VERSION 5.7 ;
  NOWIREEXTENSIONATPIN ON ;
  DIVIDERCHAR "/" ;
  BUSBITCHARS "[]" ;
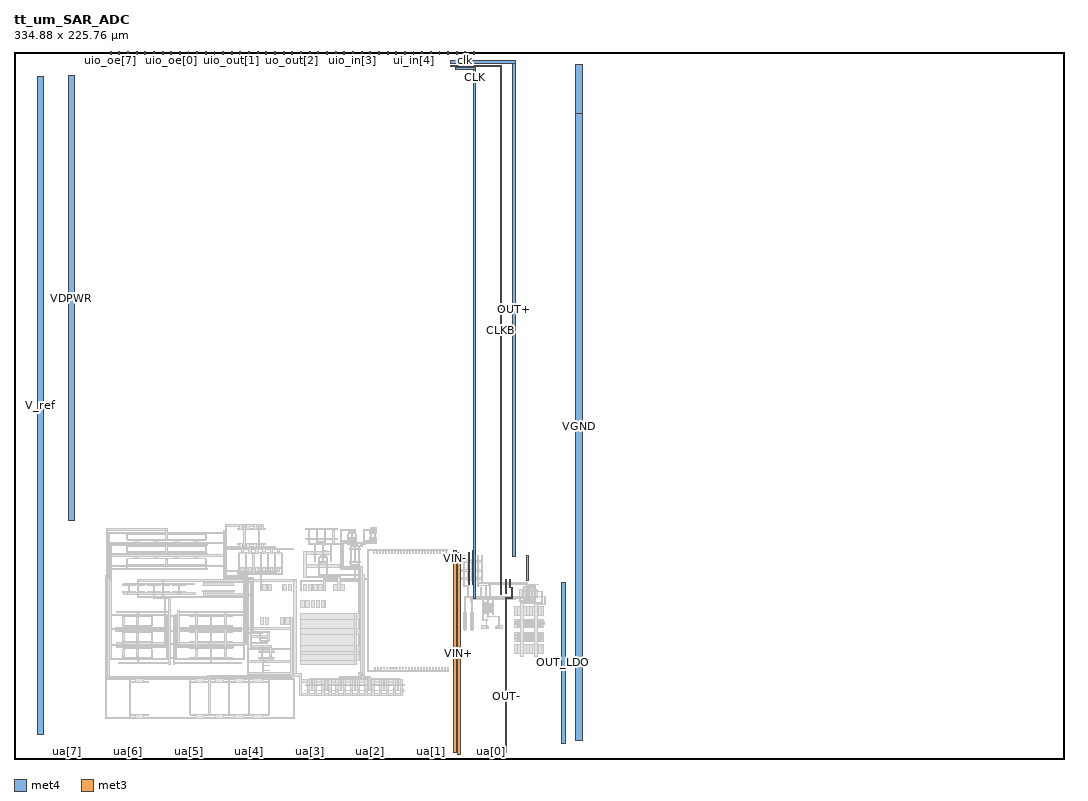
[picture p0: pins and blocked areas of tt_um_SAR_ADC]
MACRO tt_um_SAR_ADC
  CLASS BLOCK ;
  FOREIGN tt_um_SAR_ADC ;
  ORIGIN 0.000 0.000 ;
  SIZE 334.880 BY 225.760 ;
  PIN clk
    DIRECTION INPUT ;
    USE SIGNAL ;
    PORT
      LAYER met4 ;
        RECT 143.830 224.760 144.130 225.760 ;
    END
  END clk
  PIN ena
    DIRECTION INPUT ;
    USE SIGNAL ;
    PORT
      LAYER met4 ;
        RECT 146.590 224.760 146.890 225.760 ;
    END
  END ena
  PIN rst_n
    DIRECTION INPUT ;
    USE SIGNAL ;
    PORT
      LAYER met4 ;
        RECT 141.070 224.760 141.370 225.760 ;
    END
  END rst_n
  PIN ua[0]
    DIRECTION INOUT ;
    USE SIGNAL ;
    PORT
      LAYER met4 ;
        RECT 151.810 0.000 152.710 1.000 ;
    END
  END ua[0]
  PIN ua[1]
    DIRECTION INOUT ;
    USE SIGNAL ;
    PORT
      LAYER met4 ;
        RECT 132.490 0.000 133.390 1.000 ;
    END
  END ua[1]
  PIN ua[2]
    DIRECTION INOUT ;
    USE SIGNAL ;
    PORT
      LAYER met4 ;
        RECT 113.170 0.000 114.070 1.000 ;
    END
  END ua[2]
  PIN ua[3]
    DIRECTION INOUT ;
    USE SIGNAL ;
    PORT
      LAYER met4 ;
        RECT 93.850 0.000 94.750 1.000 ;
    END
  END ua[3]
  PIN ua[4]
    DIRECTION INOUT ;
    USE SIGNAL ;
    PORT
      LAYER met4 ;
        RECT 74.530 0.000 75.430 1.000 ;
    END
  END ua[4]
  PIN ua[5]
    DIRECTION INOUT ;
    USE SIGNAL ;
    PORT
      LAYER met4 ;
        RECT 55.210 0.000 56.110 1.000 ;
    END
  END ua[5]
  PIN ua[6]
    DIRECTION INOUT ;
    USE SIGNAL ;
    PORT
      LAYER met4 ;
        RECT 35.890 0.000 36.790 1.000 ;
    END
  END ua[6]
  PIN ua[7]
    DIRECTION INOUT ;
    USE SIGNAL ;
    PORT
      LAYER met4 ;
        RECT 16.570 0.000 17.470 1.000 ;
    END
  END ua[7]
  PIN ui_in[0]
    DIRECTION INPUT ;
    USE SIGNAL ;
    PORT
      LAYER met4 ;
        RECT 138.310 224.760 138.610 225.760 ;
    END
  END ui_in[0]
  PIN ui_in[1]
    DIRECTION INPUT ;
    USE SIGNAL ;
    PORT
      LAYER met4 ;
        RECT 135.550 224.760 135.850 225.760 ;
    END
  END ui_in[1]
  PIN ui_in[2]
    DIRECTION INPUT ;
    USE SIGNAL ;
    PORT
      LAYER met4 ;
        RECT 132.790 224.760 133.090 225.760 ;
    END
  END ui_in[2]
  PIN ui_in[3]
    DIRECTION INPUT ;
    USE SIGNAL ;
    PORT
      LAYER met4 ;
        RECT 130.030 224.760 130.330 225.760 ;
    END
  END ui_in[3]
  PIN ui_in[4]
    DIRECTION INPUT ;
    USE SIGNAL ;
    PORT
      LAYER met4 ;
        RECT 127.270 224.760 127.570 225.760 ;
    END
  END ui_in[4]
  PIN ui_in[5]
    DIRECTION INPUT ;
    USE SIGNAL ;
    PORT
      LAYER met4 ;
        RECT 124.510 224.760 124.810 225.760 ;
    END
  END ui_in[5]
  PIN ui_in[6]
    DIRECTION INPUT ;
    USE SIGNAL ;
    PORT
      LAYER met4 ;
        RECT 121.750 224.760 122.050 225.760 ;
    END
  END ui_in[6]
  PIN ui_in[7]
    DIRECTION INPUT ;
    USE SIGNAL ;
    PORT
      LAYER met4 ;
        RECT 118.990 224.760 119.290 225.760 ;
    END
  END ui_in[7]
  PIN uio_in[0]
    DIRECTION INPUT ;
    USE SIGNAL ;
    PORT
      LAYER met4 ;
        RECT 116.230 224.760 116.530 225.760 ;
    END
  END uio_in[0]
  PIN uio_in[1]
    DIRECTION INPUT ;
    USE SIGNAL ;
    PORT
      LAYER met4 ;
        RECT 113.470 224.760 113.770 225.760 ;
    END
  END uio_in[1]
  PIN uio_in[2]
    DIRECTION INPUT ;
    USE SIGNAL ;
    PORT
      LAYER met4 ;
        RECT 110.710 224.760 111.010 225.760 ;
    END
  END uio_in[2]
  PIN uio_in[3]
    DIRECTION INPUT ;
    USE SIGNAL ;
    PORT
      LAYER met4 ;
        RECT 107.950 224.760 108.250 225.760 ;
    END
  END uio_in[3]
  PIN uio_in[4]
    DIRECTION INPUT ;
    USE SIGNAL ;
    PORT
      LAYER met4 ;
        RECT 105.190 224.760 105.490 225.760 ;
    END
  END uio_in[4]
  PIN uio_in[5]
    DIRECTION INPUT ;
    USE SIGNAL ;
    PORT
      LAYER met4 ;
        RECT 102.430 224.760 102.730 225.760 ;
    END
  END uio_in[5]
  PIN uio_in[6]
    DIRECTION INPUT ;
    USE SIGNAL ;
    PORT
      LAYER met4 ;
        RECT 99.670 224.760 99.970 225.760 ;
    END
  END uio_in[6]
  PIN uio_in[7]
    DIRECTION INPUT ;
    USE SIGNAL ;
    PORT
      LAYER met4 ;
        RECT 96.910 224.760 97.210 225.760 ;
    END
  END uio_in[7]
  PIN uio_oe[0]
    DIRECTION OUTPUT ;
    USE SIGNAL ;
    PORT
      LAYER met4 ;
        RECT 49.990 224.760 50.290 225.760 ;
    END
  END uio_oe[0]
  PIN uio_oe[1]
    DIRECTION OUTPUT ;
    USE SIGNAL ;
    PORT
      LAYER met4 ;
        RECT 47.230 224.760 47.530 225.760 ;
    END
  END uio_oe[1]
  PIN uio_oe[2]
    DIRECTION OUTPUT ;
    USE SIGNAL ;
    PORT
      LAYER met4 ;
        RECT 44.470 224.760 44.770 225.760 ;
    END
  END uio_oe[2]
  PIN uio_oe[3]
    DIRECTION OUTPUT ;
    USE SIGNAL ;
    PORT
      LAYER met4 ;
        RECT 41.710 224.760 42.010 225.760 ;
    END
  END uio_oe[3]
  PIN uio_oe[4]
    DIRECTION OUTPUT ;
    USE SIGNAL ;
    PORT
      LAYER met4 ;
        RECT 38.950 224.760 39.250 225.760 ;
    END
  END uio_oe[4]
  PIN uio_oe[5]
    DIRECTION OUTPUT ;
    USE SIGNAL ;
    PORT
      LAYER met4 ;
        RECT 36.190 224.760 36.490 225.760 ;
    END
  END uio_oe[5]
  PIN uio_oe[6]
    DIRECTION OUTPUT ;
    USE SIGNAL ;
    PORT
      LAYER met4 ;
        RECT 33.430 224.760 33.730 225.760 ;
    END
  END uio_oe[6]
  PIN uio_oe[7]
    DIRECTION OUTPUT ;
    USE SIGNAL ;
    PORT
      LAYER met4 ;
        RECT 30.670 224.760 30.970 225.760 ;
    END
  END uio_oe[7]
  PIN uio_out[0]
    DIRECTION OUTPUT ;
    USE SIGNAL ;
    PORT
      LAYER met4 ;
        RECT 72.070 224.760 72.370 225.760 ;
    END
  END uio_out[0]
  PIN uio_out[1]
    DIRECTION OUTPUT ;
    USE SIGNAL ;
    PORT
      LAYER met4 ;
        RECT 69.310 224.760 69.610 225.760 ;
    END
  END uio_out[1]
  PIN uio_out[2]
    DIRECTION OUTPUT ;
    USE SIGNAL ;
    PORT
      LAYER met4 ;
        RECT 66.550 224.760 66.850 225.760 ;
    END
  END uio_out[2]
  PIN uio_out[3]
    DIRECTION OUTPUT ;
    USE SIGNAL ;
    PORT
      LAYER met4 ;
        RECT 63.790 224.760 64.090 225.760 ;
    END
  END uio_out[3]
  PIN uio_out[4]
    DIRECTION OUTPUT ;
    USE SIGNAL ;
    PORT
      LAYER met4 ;
        RECT 61.030 224.760 61.330 225.760 ;
    END
  END uio_out[4]
  PIN uio_out[5]
    DIRECTION OUTPUT ;
    USE SIGNAL ;
    PORT
      LAYER met4 ;
        RECT 58.270 224.760 58.570 225.760 ;
    END
  END uio_out[5]
  PIN uio_out[6]
    DIRECTION OUTPUT ;
    USE SIGNAL ;
    PORT
      LAYER met4 ;
        RECT 55.510 224.760 55.810 225.760 ;
    END
  END uio_out[6]
  PIN uio_out[7]
    DIRECTION OUTPUT ;
    USE SIGNAL ;
    PORT
      LAYER met4 ;
        RECT 52.750 224.760 53.050 225.760 ;
    END
  END uio_out[7]
  PIN uo_out[0]
    DIRECTION OUTPUT ;
    USE SIGNAL ;
    PORT
      LAYER met4 ;
        RECT 94.150 224.760 94.450 225.760 ;
    END
  END uo_out[0]
  PIN uo_out[1]
    DIRECTION OUTPUT ;
    USE SIGNAL ;
    PORT
      LAYER met4 ;
        RECT 91.390 224.760 91.690 225.760 ;
    END
  END uo_out[1]
  PIN uo_out[2]
    DIRECTION OUTPUT ;
    USE SIGNAL ;
    PORT
      LAYER met4 ;
        RECT 88.630 224.760 88.930 225.760 ;
    END
  END uo_out[2]
  PIN uo_out[3]
    DIRECTION OUTPUT ;
    USE SIGNAL ;
    PORT
      LAYER met4 ;
        RECT 85.870 224.760 86.170 225.760 ;
    END
  END uo_out[3]
  PIN uo_out[4]
    DIRECTION OUTPUT ;
    USE SIGNAL ;
    PORT
      LAYER met4 ;
        RECT 83.110 224.760 83.410 225.760 ;
    END
  END uo_out[4]
  PIN uo_out[5]
    DIRECTION OUTPUT ;
    USE SIGNAL ;
    PORT
      LAYER met4 ;
        RECT 80.350 224.760 80.650 225.760 ;
    END
  END uo_out[5]
  PIN uo_out[6]
    DIRECTION OUTPUT ;
    USE SIGNAL ;
    PORT
      LAYER met4 ;
        RECT 77.590 224.760 77.890 225.760 ;
    END
  END uo_out[6]
  PIN uo_out[7]
    DIRECTION OUTPUT ;
    USE SIGNAL ;
    PORT
      LAYER met4 ;
        RECT 74.830 224.760 75.130 225.760 ;
    END
  END uo_out[7]
  PIN V_ref
    DIRECTION INPUT ;
    USE POWER ;
    PORT
      LAYER met4 ;
        RECT 7.415 7.755 9.420 217.765 ;
    END
  END V_ref
  PIN VDPWR
    DIRECTION INOUT ;
    USE POWER ;
    PORT
      LAYER met4 ;
        RECT 17.400 75.940 19.400 218.050 ;
    END
  END VDPWR
  PIN VGND
    DIRECTION INOUT ;
    USE GROUND ;
    PORT
      LAYER met4 ;
        RECT 179.160 205.890 181.165 221.595 ;
        RECT 179.160 5.930 181.160 205.890 ;
    END
  END VGND
  PIN CLK
    DIRECTION INOUT ;
    USE CLOCK ;
    ANTENNAGATEAREA 1.497000 ;
    PORT
      LAYER met4 ;
        RECT 140.655 220.015 147.075 220.395 ;
        RECT 146.695 51.275 147.075 220.015 ;
    END
  END CLK
  PIN CLKB
    DIRECTION INOUT ;
    USE CLOCK ;
    ANTENNAGATEAREA 1.260000 ;
    PORT
      LAYER met4 ;
        RECT 139.345 220.950 155.415 221.330 ;
        RECT 155.035 52.380 155.415 220.950 ;
    END
  END CLKB
  PIN OUT_LDO
    DIRECTION OUTPUT ;
    USE SIGNAL ;
    ANTENNAGATEAREA 17.223999 ;
    ANTENNADIFFAREA 346.940796 ;
    PORT
      LAYER met4 ;
        RECT 174.550 5.045 175.860 56.430 ;
    END
  END OUT_LDO
  PIN OUT-
    DIRECTION OUTPUT ;
    USE SIGNAL ;
    ANTENNAGATEAREA 23.000000 ;
    ANTENNADIFFAREA 4.522500 ;
    PORT
      LAYER met3 ;
        RECT 156.620 57.065 156.950 57.395 ;
        RECT 158.115 57.065 158.445 57.395 ;
        RECT 163.325 57.065 164.225 65.055 ;
        RECT 156.635 53.150 156.935 57.065 ;
        RECT 158.130 54.850 158.430 57.065 ;
        RECT 158.130 54.550 158.970 54.850 ;
        RECT 158.670 54.050 158.970 54.550 ;
        RECT 158.655 53.720 158.985 54.050 ;
        RECT 156.620 52.820 156.950 53.150 ;
        RECT 156.690 51.490 157.175 51.540 ;
        RECT 158.670 51.490 158.970 53.720 ;
        RECT 156.690 51.190 158.970 51.490 ;
        RECT 156.690 37.435 157.175 51.190 ;
        RECT 156.690 2.170 157.170 37.435 ;
    END
  END OUT-
  PIN VIN+
    DIRECTION INPUT ;
    USE SIGNAL ;
    ANTENNAGATEAREA 4.620000 ;
    PORT
      LAYER met3 ;
        RECT 141.430 1.525 142.315 65.745 ;
        RECT 144.870 65.400 145.240 65.770 ;
        RECT 144.910 65.055 145.240 65.400 ;
        RECT 144.905 64.915 145.240 65.055 ;
        RECT 144.890 64.665 145.240 64.915 ;
        RECT 144.890 64.585 145.220 64.665 ;
        RECT 144.905 55.975 145.205 64.585 ;
        RECT 144.890 55.645 145.220 55.975 ;
        RECT 144.905 55.590 145.205 55.645 ;
    END
  END VIN+
  PIN VIN-
    DIRECTION OUTPUT ;
    USE SIGNAL ;
    ANTENNAGATEAREA 4.620000 ;
    PORT
      LAYER met3 ;
        RECT 140.155 2.045 141.040 66.515 ;
        RECT 146.305 65.785 146.675 66.555 ;
        RECT 146.340 65.055 146.640 65.785 ;
        RECT 146.320 64.750 146.640 65.055 ;
        RECT 146.320 64.070 146.620 64.750 ;
        RECT 146.305 63.740 146.635 64.070 ;
        RECT 146.320 56.820 146.620 63.740 ;
        RECT 146.305 56.490 146.635 56.820 ;
        RECT 146.320 55.590 146.620 56.490 ;
    END
  END VIN-
  PIN OUT+
    DIRECTION OUTPUT ;
    USE SIGNAL ;
    ANTENNAGATEAREA 23.000000 ;
    ANTENNADIFFAREA 5.772500 ;
    PORT
      LAYER met4 ;
        RECT 139.240 221.805 159.865 222.705 ;
        RECT 158.965 64.660 159.865 221.805 ;
    END
  END OUT+
  OBS
      LAYER pwell ;
        RECT 161.320 51.435 162.260 54.195 ;
        RECT 162.270 51.435 163.210 54.195 ;
        RECT 163.220 51.435 164.160 54.195 ;
        RECT 164.170 51.435 165.110 54.195 ;
        RECT 165.120 51.435 166.060 54.195 ;
        RECT 166.070 51.435 167.010 54.195 ;
        RECT 143.395 41.305 144.335 46.565 ;
        RECT 145.485 41.305 146.425 46.565 ;
        RECT 159.540 45.840 160.480 48.600 ;
        RECT 160.490 45.840 161.430 48.600 ;
        RECT 161.440 45.840 162.380 48.600 ;
        RECT 162.390 45.840 163.330 48.600 ;
        RECT 163.340 45.840 164.280 48.600 ;
        RECT 164.290 45.840 165.230 48.600 ;
        RECT 165.240 45.840 166.180 48.600 ;
        RECT 166.190 45.840 167.130 48.600 ;
        RECT 167.140 45.840 168.080 48.600 ;
        RECT 168.090 45.840 169.030 48.600 ;
        RECT 149.165 41.695 150.955 42.455 ;
        RECT 154.045 41.695 155.835 42.455 ;
        RECT 159.540 41.880 160.480 44.640 ;
        RECT 160.490 41.880 161.430 44.640 ;
        RECT 161.440 41.880 162.380 44.640 ;
        RECT 162.390 41.880 163.330 44.640 ;
        RECT 163.340 41.880 164.280 44.640 ;
        RECT 164.290 41.880 165.230 44.640 ;
        RECT 165.240 41.880 166.180 44.640 ;
        RECT 166.190 41.880 167.130 44.640 ;
        RECT 167.140 41.880 168.080 44.640 ;
        RECT 168.090 41.880 169.030 44.640 ;
        RECT 159.540 37.610 160.480 40.370 ;
        RECT 160.490 37.610 161.430 40.370 ;
        RECT 161.440 37.610 162.380 40.370 ;
        RECT 162.390 37.610 163.330 40.370 ;
        RECT 163.340 37.610 164.280 40.370 ;
        RECT 164.290 37.610 165.230 40.370 ;
        RECT 165.240 37.610 166.180 40.370 ;
        RECT 166.190 37.610 167.130 40.370 ;
        RECT 167.140 37.610 168.080 40.370 ;
        RECT 168.090 37.610 169.030 40.370 ;
        RECT 159.540 33.650 160.480 36.410 ;
        RECT 160.490 33.650 161.430 36.410 ;
        RECT 161.440 33.650 162.380 36.410 ;
        RECT 162.390 33.650 163.330 36.410 ;
        RECT 163.340 33.650 164.280 36.410 ;
        RECT 164.290 33.650 165.230 36.410 ;
        RECT 165.240 33.650 166.180 36.410 ;
        RECT 166.190 33.650 167.130 36.410 ;
        RECT 167.140 33.650 168.080 36.410 ;
        RECT 168.090 33.650 169.030 36.410 ;
      LAYER li1 ;
        RECT 71.380 73.375 73.380 73.545 ;
        RECT 73.670 73.375 75.670 73.545 ;
        RECT 75.960 73.375 77.960 73.545 ;
        RECT 78.250 73.375 80.250 73.545 ;
        RECT 93.010 73.285 94.010 73.455 ;
        RECT 94.300 73.285 95.300 73.455 ;
        RECT 95.590 73.285 96.590 73.455 ;
        RECT 96.880 73.285 97.880 73.455 ;
        RECT 98.170 73.285 99.170 73.455 ;
        RECT 99.460 73.285 100.460 73.455 ;
        RECT 100.750 73.285 101.750 73.455 ;
        RECT 102.040 73.285 103.040 73.455 ;
        RECT 36.205 71.615 42.205 71.785 ;
        RECT 42.495 71.615 48.495 71.785 ;
        RECT 48.785 71.615 54.785 71.785 ;
        RECT 55.075 71.615 61.075 71.785 ;
        RECT 35.975 70.110 36.145 71.400 ;
        RECT 48.555 70.110 48.725 71.400 ;
        RECT 61.135 70.110 61.305 71.400 ;
        RECT 36.205 69.725 42.205 69.895 ;
        RECT 42.495 69.725 48.495 69.895 ;
        RECT 48.785 69.725 54.785 69.895 ;
        RECT 55.075 69.725 61.075 69.895 ;
        RECT 73.440 68.870 73.610 73.160 ;
        RECT 78.020 68.870 78.190 73.160 ;
        RECT 94.070 70.530 94.240 73.070 ;
        RECT 96.650 70.530 96.820 73.070 ;
        RECT 99.230 70.530 99.400 73.070 ;
        RECT 101.810 70.530 101.980 73.070 ;
        RECT 106.750 71.935 107.100 72.105 ;
        RECT 107.390 71.935 107.740 72.105 ;
        RECT 108.030 71.935 108.380 72.105 ;
        RECT 108.670 71.935 109.020 72.105 ;
        RECT 113.470 71.935 113.820 72.105 ;
        RECT 114.110 71.935 114.460 72.105 ;
        RECT 114.750 71.935 115.100 72.105 ;
        RECT 115.390 71.935 115.740 72.105 ;
        RECT 106.520 70.800 106.690 71.720 ;
        RECT 107.800 70.800 107.970 71.720 ;
        RECT 109.080 70.800 109.250 71.720 ;
        RECT 113.880 70.800 114.050 71.720 ;
        RECT 115.160 70.800 115.330 71.720 ;
        RECT 106.750 70.415 107.100 70.585 ;
        RECT 107.390 70.415 107.740 70.585 ;
        RECT 108.030 70.415 108.380 70.585 ;
        RECT 108.670 70.415 109.020 70.585 ;
        RECT 113.470 70.415 113.820 70.585 ;
        RECT 114.110 70.415 114.460 70.585 ;
        RECT 114.750 70.415 115.100 70.585 ;
        RECT 115.390 70.415 115.740 70.585 ;
        RECT 93.010 70.145 94.010 70.315 ;
        RECT 94.300 70.145 95.300 70.315 ;
        RECT 95.590 70.145 96.590 70.315 ;
        RECT 96.880 70.145 97.880 70.315 ;
        RECT 98.170 70.145 99.170 70.315 ;
        RECT 99.460 70.145 100.460 70.315 ;
        RECT 100.750 70.145 101.750 70.315 ;
        RECT 102.040 70.145 103.040 70.315 ;
        RECT 71.380 68.485 73.380 68.655 ;
        RECT 73.670 68.485 75.670 68.655 ;
        RECT 75.960 68.485 77.960 68.655 ;
        RECT 78.250 68.485 80.250 68.655 ;
        RECT 36.205 67.725 42.205 67.895 ;
        RECT 42.495 67.725 48.495 67.895 ;
        RECT 48.785 67.725 54.785 67.895 ;
        RECT 55.075 67.725 61.075 67.895 ;
        RECT 35.975 66.220 36.145 67.510 ;
        RECT 48.555 66.220 48.725 67.510 ;
        RECT 61.135 66.220 61.305 67.510 ;
        RECT 106.870 66.785 107.220 66.955 ;
        RECT 107.510 66.785 107.860 66.955 ;
        RECT 108.150 66.785 108.500 66.955 ;
        RECT 108.790 66.785 109.140 66.955 ;
        RECT 109.430 66.785 109.780 66.955 ;
        RECT 110.070 66.785 110.420 66.955 ;
        RECT 36.205 65.835 42.205 66.005 ;
        RECT 42.495 65.835 48.495 66.005 ;
        RECT 48.785 65.835 54.785 66.005 ;
        RECT 55.075 65.835 61.075 66.005 ;
        RECT 71.935 65.750 73.935 65.920 ;
        RECT 74.225 65.750 76.225 65.920 ;
        RECT 76.515 65.750 78.515 65.920 ;
        RECT 78.805 65.750 80.805 65.920 ;
        RECT 81.095 65.750 83.095 65.920 ;
        RECT 83.385 65.750 85.385 65.920 ;
        RECT 36.205 63.835 42.205 64.005 ;
        RECT 42.495 63.835 48.495 64.005 ;
        RECT 48.785 63.835 54.785 64.005 ;
        RECT 55.075 63.835 61.075 64.005 ;
        RECT 35.975 62.330 36.145 63.620 ;
        RECT 48.555 62.330 48.725 63.620 ;
        RECT 61.135 62.330 61.305 63.620 ;
        RECT 36.205 61.945 42.205 62.115 ;
        RECT 42.495 61.945 48.495 62.115 ;
        RECT 48.785 61.945 54.785 62.115 ;
        RECT 55.075 61.945 61.075 62.115 ;
        RECT 71.705 61.245 71.875 65.535 ;
        RECT 73.995 61.245 74.165 65.535 ;
        RECT 76.285 61.245 76.455 65.535 ;
        RECT 78.575 61.245 78.745 65.535 ;
        RECT 80.865 61.245 81.035 65.535 ;
        RECT 83.155 61.245 83.325 65.535 ;
        RECT 85.445 61.245 85.615 65.535 ;
        RECT 97.480 64.440 98.480 64.610 ;
        RECT 98.770 64.440 99.770 64.610 ;
        RECT 95.960 62.980 96.130 64.270 ;
        RECT 97.250 62.980 97.420 64.270 ;
        RECT 98.540 62.980 98.710 64.270 ;
        RECT 99.830 62.980 100.000 64.270 ;
        RECT 101.120 62.980 101.290 64.270 ;
        RECT 107.280 63.075 107.450 66.615 ;
        RECT 108.560 63.075 108.730 66.615 ;
        RECT 109.840 63.075 110.010 66.615 ;
        RECT 114.630 65.590 114.960 65.760 ;
        RECT 115.590 65.590 115.920 65.760 ;
        RECT 116.550 65.590 116.880 65.760 ;
        RECT 117.510 65.590 117.840 65.760 ;
        RECT 118.470 65.590 118.800 65.760 ;
        RECT 119.430 65.590 119.760 65.760 ;
        RECT 120.390 65.590 120.720 65.760 ;
        RECT 121.350 65.590 121.680 65.760 ;
        RECT 122.310 65.590 122.640 65.760 ;
        RECT 123.270 65.590 123.600 65.760 ;
        RECT 124.230 65.590 124.560 65.760 ;
        RECT 125.190 65.590 125.520 65.760 ;
        RECT 126.150 65.590 126.480 65.760 ;
        RECT 127.110 65.590 127.440 65.760 ;
        RECT 128.070 65.590 128.400 65.760 ;
        RECT 129.030 65.590 129.360 65.760 ;
        RECT 129.990 65.590 130.320 65.760 ;
        RECT 130.950 65.590 131.280 65.760 ;
        RECT 131.910 65.590 132.240 65.760 ;
        RECT 132.870 65.590 133.200 65.760 ;
        RECT 133.830 65.590 134.160 65.760 ;
        RECT 134.790 65.590 135.120 65.760 ;
        RECT 135.750 65.590 136.080 65.760 ;
        RECT 136.710 65.590 137.040 65.760 ;
        RECT 137.670 65.590 138.000 65.760 ;
        RECT 97.480 62.640 98.480 62.810 ;
        RECT 98.770 62.640 99.770 62.810 ;
        RECT 106.870 62.735 107.220 62.905 ;
        RECT 107.510 62.735 107.860 62.905 ;
        RECT 108.150 62.735 108.500 62.905 ;
        RECT 108.790 62.735 109.140 62.905 ;
        RECT 109.430 62.735 109.780 62.905 ;
        RECT 110.070 62.735 110.420 62.905 ;
        RECT 71.935 60.860 73.935 61.030 ;
        RECT 74.225 60.860 76.225 61.030 ;
        RECT 76.515 60.860 78.515 61.030 ;
        RECT 78.805 60.860 80.805 61.030 ;
        RECT 81.095 60.860 83.095 61.030 ;
        RECT 83.385 60.860 85.385 61.030 ;
        RECT 144.550 56.980 144.720 63.580 ;
        RECT 145.180 56.980 145.350 63.580 ;
        RECT 145.810 56.980 145.980 63.580 ;
        RECT 146.440 56.980 146.610 63.580 ;
        RECT 147.070 56.980 147.240 63.580 ;
        RECT 34.495 55.350 36.495 55.520 ;
        RECT 36.785 55.350 38.785 55.520 ;
        RECT 39.635 55.350 41.635 55.520 ;
        RECT 42.485 55.350 44.485 55.520 ;
        RECT 44.775 55.350 46.775 55.520 ;
        RECT 47.625 55.350 49.625 55.520 ;
        RECT 50.475 55.350 52.475 55.520 ;
        RECT 52.765 55.350 54.765 55.520 ;
        RECT 60.215 55.285 61.215 55.455 ;
        RECT 61.505 55.285 62.505 55.455 ;
        RECT 62.795 55.285 63.795 55.455 ;
        RECT 64.085 55.285 65.085 55.455 ;
        RECT 65.375 55.285 66.375 55.455 ;
        RECT 66.665 55.285 67.665 55.455 ;
        RECT 67.955 55.285 68.955 55.455 ;
        RECT 69.245 55.285 70.245 55.455 ;
        RECT 36.555 53.595 36.725 55.135 ;
        RECT 39.405 53.595 39.575 55.135 ;
        RECT 44.545 53.595 44.715 55.135 ;
        RECT 47.395 53.595 47.565 55.135 ;
        RECT 52.535 53.595 52.705 55.135 ;
        RECT 78.485 53.635 78.835 55.795 ;
        RECT 79.315 53.635 79.665 55.795 ;
        RECT 80.145 53.635 80.495 55.795 ;
        RECT 80.975 53.635 81.325 55.795 ;
        RECT 81.805 53.635 82.155 55.795 ;
        RECT 85.775 53.635 86.125 55.795 ;
        RECT 86.605 53.635 86.955 55.795 ;
        RECT 87.435 53.635 87.785 55.795 ;
        RECT 88.265 53.635 88.615 55.795 ;
        RECT 91.405 53.635 91.755 55.795 ;
        RECT 92.235 53.635 92.585 55.795 ;
        RECT 93.065 53.635 93.415 55.795 ;
        RECT 93.895 53.635 94.245 55.795 ;
        RECT 94.725 53.635 95.075 55.795 ;
        RECT 95.555 53.635 95.905 55.795 ;
        RECT 96.385 53.635 96.735 55.795 ;
        RECT 97.215 53.635 97.565 55.795 ;
        RECT 98.045 53.635 98.395 55.795 ;
        RECT 98.875 53.635 99.225 55.795 ;
        RECT 102.015 53.635 102.365 55.795 ;
        RECT 105.155 53.635 105.505 55.795 ;
        RECT 162.575 54.275 162.905 54.505 ;
        RECT 163.525 54.275 163.855 54.505 ;
        RECT 164.475 54.275 164.805 54.505 ;
        RECT 165.425 54.275 165.755 54.505 ;
        RECT 60.215 53.395 61.215 53.565 ;
        RECT 61.505 53.395 62.505 53.565 ;
        RECT 62.795 53.395 63.795 53.565 ;
        RECT 64.085 53.395 65.085 53.565 ;
        RECT 65.375 53.395 66.375 53.565 ;
        RECT 66.665 53.395 67.665 53.565 ;
        RECT 67.955 53.395 68.955 53.565 ;
        RECT 69.245 53.395 70.245 53.565 ;
        RECT 34.495 53.210 36.495 53.380 ;
        RECT 36.785 53.210 38.785 53.380 ;
        RECT 39.635 53.210 41.635 53.380 ;
        RECT 42.485 53.210 44.485 53.380 ;
        RECT 44.775 53.210 46.775 53.380 ;
        RECT 47.625 53.210 49.625 53.380 ;
        RECT 50.475 53.210 52.475 53.380 ;
        RECT 52.765 53.210 54.765 53.380 ;
        RECT 144.645 53.160 144.815 53.660 ;
        RECT 148.770 53.190 148.940 53.610 ;
        RECT 162.440 51.565 162.610 54.065 ;
        RECT 163.390 51.565 163.560 54.065 ;
        RECT 164.340 51.565 164.510 54.065 ;
        RECT 165.290 51.565 165.460 54.065 ;
        RECT 162.575 51.125 162.905 51.355 ;
        RECT 163.525 51.125 163.855 51.355 ;
        RECT 164.475 51.125 164.805 51.355 ;
        RECT 165.425 51.125 165.755 51.355 ;
        RECT 91.405 48.315 91.755 50.475 ;
        RECT 92.235 48.315 92.585 50.475 ;
        RECT 93.065 48.315 93.415 50.475 ;
        RECT 93.895 48.315 94.245 50.475 ;
        RECT 94.725 48.315 95.075 50.475 ;
        RECT 95.555 48.315 95.905 50.475 ;
        RECT 96.385 48.315 96.735 50.475 ;
        RECT 97.215 48.315 97.565 50.475 ;
        RECT 98.045 48.315 98.395 50.475 ;
        RECT 98.875 48.315 99.225 50.475 ;
        RECT 143.625 49.740 143.975 49.970 ;
        RECT 145.935 49.740 146.285 49.970 ;
        RECT 150.110 48.850 150.460 49.080 ;
        RECT 150.740 48.850 151.090 49.080 ;
        RECT 151.370 48.850 151.720 49.080 ;
        RECT 152.000 48.850 152.350 49.080 ;
        RECT 143.625 48.540 143.975 48.770 ;
        RECT 145.935 48.540 146.285 48.770 ;
        RECT 149.885 47.640 150.055 48.640 ;
        RECT 150.515 47.640 150.685 48.640 ;
        RECT 151.145 47.640 151.315 48.640 ;
        RECT 151.775 47.640 151.945 48.640 ;
        RECT 152.405 47.640 152.575 48.640 ;
        RECT 150.110 47.200 150.460 47.430 ;
        RECT 150.740 47.200 151.090 47.430 ;
        RECT 151.370 47.200 151.720 47.430 ;
        RECT 152.000 47.200 152.350 47.430 ;
        RECT 143.700 46.645 144.030 46.875 ;
        RECT 145.790 46.645 146.120 46.875 ;
        RECT 35.025 45.320 37.025 45.490 ;
        RECT 37.315 45.320 39.315 45.490 ;
        RECT 39.605 45.320 41.605 45.490 ;
        RECT 41.895 45.320 43.895 45.490 ;
        RECT 56.115 45.320 58.115 45.490 ;
        RECT 58.405 45.320 60.405 45.490 ;
        RECT 60.695 45.320 62.695 45.490 ;
        RECT 62.985 45.320 64.985 45.490 ;
        RECT 65.275 45.320 67.275 45.490 ;
        RECT 67.565 45.320 69.565 45.490 ;
        RECT 34.795 42.610 34.965 45.150 ;
        RECT 39.375 42.610 39.545 45.150 ;
        RECT 43.955 42.610 44.125 45.150 ;
        RECT 58.175 42.610 58.345 45.150 ;
        RECT 62.755 42.610 62.925 45.150 ;
        RECT 67.335 42.610 67.505 45.150 ;
        RECT 78.485 42.885 78.835 45.045 ;
        RECT 79.315 42.885 79.665 45.045 ;
        RECT 80.145 42.885 80.495 45.045 ;
        RECT 80.975 42.885 81.325 45.045 ;
        RECT 84.945 42.885 85.295 45.045 ;
        RECT 85.775 42.885 86.125 45.045 ;
        RECT 86.605 42.885 86.955 45.045 ;
        RECT 87.435 42.885 87.785 45.045 ;
        RECT 88.265 42.885 88.615 45.045 ;
        RECT 35.025 42.270 37.025 42.440 ;
        RECT 37.315 42.270 39.315 42.440 ;
        RECT 39.605 42.270 41.605 42.440 ;
        RECT 41.895 42.270 43.895 42.440 ;
        RECT 56.115 42.270 58.115 42.440 ;
        RECT 58.405 42.270 60.405 42.440 ;
        RECT 60.695 42.270 62.695 42.440 ;
        RECT 62.985 42.270 64.985 42.440 ;
        RECT 65.275 42.270 67.275 42.440 ;
        RECT 67.565 42.270 69.565 42.440 ;
        RECT 151.135 41.825 151.305 42.325 ;
        RECT 153.695 41.825 153.865 42.325 ;
        RECT 161.090 42.010 161.260 44.510 ;
        RECT 162.040 42.010 162.210 44.510 ;
        RECT 162.990 42.010 163.160 44.510 ;
        RECT 163.940 42.010 164.110 44.510 ;
        RECT 164.890 42.010 165.060 44.510 ;
        RECT 165.840 42.010 166.010 44.510 ;
        RECT 166.790 42.010 166.960 44.510 ;
        RECT 167.740 42.010 167.910 44.510 ;
        RECT 143.700 40.995 144.030 41.225 ;
        RECT 145.790 40.995 146.120 41.225 ;
        RECT 35.025 40.270 37.025 40.440 ;
        RECT 37.315 40.270 39.315 40.440 ;
        RECT 39.605 40.270 41.605 40.440 ;
        RECT 41.895 40.270 43.895 40.440 ;
        RECT 56.115 40.270 58.115 40.440 ;
        RECT 58.405 40.270 60.405 40.440 ;
        RECT 60.695 40.270 62.695 40.440 ;
        RECT 62.985 40.270 64.985 40.440 ;
        RECT 65.275 40.270 67.275 40.440 ;
        RECT 67.565 40.270 69.565 40.440 ;
        RECT 34.795 37.560 34.965 40.100 ;
        RECT 39.375 37.560 39.545 40.100 ;
        RECT 43.955 37.560 44.125 40.100 ;
        RECT 58.175 37.560 58.345 40.100 ;
        RECT 62.755 37.560 62.925 40.100 ;
        RECT 67.335 37.560 67.505 40.100 ;
        RECT 78.725 38.500 79.725 38.670 ;
        RECT 80.015 38.500 81.015 38.670 ;
        RECT 78.495 37.790 78.665 38.330 ;
        RECT 81.075 37.790 81.245 38.330 ;
        RECT 161.090 37.740 161.260 40.240 ;
        RECT 162.040 37.740 162.210 40.240 ;
        RECT 162.990 37.740 163.160 40.240 ;
        RECT 163.940 37.740 164.110 40.240 ;
        RECT 164.890 37.740 165.060 40.240 ;
        RECT 165.840 37.740 166.010 40.240 ;
        RECT 166.790 37.740 166.960 40.240 ;
        RECT 167.740 37.740 167.910 40.240 ;
        RECT 78.725 37.450 79.725 37.620 ;
        RECT 80.015 37.450 81.015 37.620 ;
        RECT 35.025 37.220 37.025 37.390 ;
        RECT 37.315 37.220 39.315 37.390 ;
        RECT 39.605 37.220 41.605 37.390 ;
        RECT 41.895 37.220 43.895 37.390 ;
        RECT 56.115 37.220 58.115 37.390 ;
        RECT 58.405 37.220 60.405 37.390 ;
        RECT 60.695 37.220 62.695 37.390 ;
        RECT 62.985 37.220 64.985 37.390 ;
        RECT 65.275 37.220 67.275 37.390 ;
        RECT 67.565 37.220 69.565 37.390 ;
        RECT 35.025 35.220 37.025 35.390 ;
        RECT 37.315 35.220 39.315 35.390 ;
        RECT 39.605 35.220 41.605 35.390 ;
        RECT 41.895 35.220 43.895 35.390 ;
        RECT 56.115 35.220 58.115 35.390 ;
        RECT 58.405 35.220 60.405 35.390 ;
        RECT 60.695 35.220 62.695 35.390 ;
        RECT 62.985 35.220 64.985 35.390 ;
        RECT 65.275 35.220 67.275 35.390 ;
        RECT 67.565 35.220 69.565 35.390 ;
        RECT 34.795 32.510 34.965 35.050 ;
        RECT 39.375 32.510 39.545 35.050 ;
        RECT 43.955 32.510 44.125 35.050 ;
        RECT 58.175 32.510 58.345 35.050 ;
        RECT 62.755 32.510 62.925 35.050 ;
        RECT 67.335 32.510 67.505 35.050 ;
        RECT 78.070 34.040 79.070 34.210 ;
        RECT 79.360 34.040 80.360 34.210 ;
        RECT 80.650 34.040 81.650 34.210 ;
        RECT 81.940 34.040 82.940 34.210 ;
        RECT 79.130 32.580 79.300 33.870 ;
        RECT 81.710 32.580 81.880 33.870 ;
        RECT 35.025 32.170 37.025 32.340 ;
        RECT 37.315 32.170 39.315 32.340 ;
        RECT 39.605 32.170 41.605 32.340 ;
        RECT 41.895 32.170 43.895 32.340 ;
        RECT 56.115 32.170 58.115 32.340 ;
        RECT 58.405 32.170 60.405 32.340 ;
        RECT 60.695 32.170 62.695 32.340 ;
        RECT 62.985 32.170 64.985 32.340 ;
        RECT 65.275 32.170 67.275 32.340 ;
        RECT 67.565 32.170 69.565 32.340 ;
        RECT 78.070 32.240 79.070 32.410 ;
        RECT 79.360 32.240 80.360 32.410 ;
        RECT 80.650 32.240 81.650 32.410 ;
        RECT 81.940 32.240 82.940 32.410 ;
        RECT 79.630 29.730 81.630 29.900 ;
        RECT 79.400 28.520 79.570 29.560 ;
        RECT 115.110 28.950 115.440 29.120 ;
        RECT 116.070 28.950 116.400 29.120 ;
        RECT 117.030 28.950 117.360 29.120 ;
        RECT 117.990 28.950 118.320 29.120 ;
        RECT 118.950 28.950 119.280 29.120 ;
        RECT 119.910 28.950 120.240 29.120 ;
        RECT 120.870 28.950 121.200 29.120 ;
        RECT 121.830 28.950 122.160 29.120 ;
        RECT 122.790 28.950 123.120 29.120 ;
        RECT 123.750 28.950 124.080 29.120 ;
        RECT 124.710 28.950 125.040 29.120 ;
        RECT 125.670 28.950 126.000 29.120 ;
        RECT 126.630 28.950 126.960 29.120 ;
        RECT 127.590 28.950 127.920 29.120 ;
        RECT 128.550 28.950 128.880 29.120 ;
        RECT 129.510 28.950 129.840 29.120 ;
        RECT 130.470 28.950 130.800 29.120 ;
        RECT 131.430 28.950 131.760 29.120 ;
        RECT 132.390 28.950 132.720 29.120 ;
        RECT 133.350 28.950 133.680 29.120 ;
        RECT 134.310 28.950 134.640 29.120 ;
        RECT 135.270 28.950 135.600 29.120 ;
        RECT 136.230 28.950 136.560 29.120 ;
        RECT 137.190 28.950 137.520 29.120 ;
        RECT 138.150 28.950 138.480 29.120 ;
        RECT 79.630 28.180 81.630 28.350 ;
        RECT 37.055 24.490 43.055 24.660 ;
        RECT 56.185 24.490 62.185 24.660 ;
        RECT 62.475 24.490 68.475 24.660 ;
        RECT 68.765 24.490 74.765 24.660 ;
        RECT 75.055 24.490 81.055 24.660 ;
        RECT 36.825 14.280 36.995 24.320 ;
        RECT 55.955 14.280 56.125 24.320 ;
        RECT 62.245 14.280 62.415 24.320 ;
        RECT 68.535 14.280 68.705 24.320 ;
        RECT 74.825 14.280 74.995 24.320 ;
        RECT 81.115 14.280 81.285 24.320 ;
        RECT 92.915 23.540 94.915 23.710 ;
        RECT 95.205 23.540 97.205 23.710 ;
        RECT 97.495 23.540 99.495 23.710 ;
        RECT 99.785 23.540 101.785 23.710 ;
        RECT 102.075 23.540 104.075 23.710 ;
        RECT 104.365 23.540 106.365 23.710 ;
        RECT 106.655 23.540 108.655 23.710 ;
        RECT 108.945 23.540 110.945 23.710 ;
        RECT 111.235 23.540 113.235 23.710 ;
        RECT 113.525 23.540 115.525 23.710 ;
        RECT 115.815 23.540 117.815 23.710 ;
        RECT 118.105 23.540 120.105 23.710 ;
        RECT 120.395 23.540 122.395 23.710 ;
        RECT 122.685 23.540 124.685 23.710 ;
        RECT 94.975 22.080 95.145 23.370 ;
        RECT 99.555 22.080 99.725 23.370 ;
        RECT 104.135 22.080 104.305 23.370 ;
        RECT 108.715 22.080 108.885 23.370 ;
        RECT 113.295 22.080 113.465 23.370 ;
        RECT 117.875 22.080 118.045 23.370 ;
        RECT 122.455 22.080 122.625 23.370 ;
        RECT 92.915 21.740 94.915 21.910 ;
        RECT 95.205 21.740 97.205 21.910 ;
        RECT 97.495 21.740 99.495 21.910 ;
        RECT 99.785 21.740 101.785 21.910 ;
        RECT 102.075 21.740 104.075 21.910 ;
        RECT 104.365 21.740 106.365 21.910 ;
        RECT 106.655 21.740 108.655 21.910 ;
        RECT 108.945 21.740 110.945 21.910 ;
        RECT 111.235 21.740 113.235 21.910 ;
        RECT 113.525 21.740 115.525 21.910 ;
        RECT 115.815 21.740 117.815 21.910 ;
        RECT 118.105 21.740 120.105 21.910 ;
        RECT 120.395 21.740 122.395 21.910 ;
        RECT 122.685 21.740 124.685 21.910 ;
        RECT 37.055 13.940 43.055 14.110 ;
        RECT 56.185 13.940 62.185 14.110 ;
        RECT 62.475 13.940 68.475 14.110 ;
        RECT 68.765 13.940 74.765 14.110 ;
        RECT 75.055 13.940 81.055 14.110 ;
      LAYER met1 ;
        RECT 72.080 73.575 72.720 73.650 ;
        RECT 74.360 73.575 75.000 73.650 ;
        RECT 76.605 73.575 77.245 73.650 ;
        RECT 78.930 73.575 79.570 73.650 ;
        RECT 71.400 73.345 73.360 73.575 ;
        RECT 73.690 73.345 75.650 73.575 ;
        RECT 75.980 73.345 77.940 73.575 ;
        RECT 78.270 73.345 80.230 73.575 ;
        RECT 72.080 73.280 72.720 73.345 ;
        RECT 74.360 73.280 75.000 73.345 ;
        RECT 76.605 73.280 77.245 73.345 ;
        RECT 78.930 73.280 79.570 73.345 ;
        RECT 93.030 73.255 103.020 73.485 ;
        RECT 73.410 73.080 73.640 73.140 ;
        RECT 77.990 73.080 78.220 73.140 ;
        RECT 38.585 71.815 39.865 72.375 ;
        RECT 44.865 71.815 46.145 72.375 ;
        RECT 51.140 71.815 52.420 72.375 ;
        RECT 57.425 71.815 58.705 72.375 ;
        RECT 36.225 71.585 42.185 71.815 ;
        RECT 42.515 71.585 48.475 71.815 ;
        RECT 48.805 71.585 54.765 71.815 ;
        RECT 55.095 71.585 61.055 71.815 ;
        RECT 35.945 71.320 36.175 71.380 ;
        RECT 48.525 71.320 48.755 71.380 ;
        RECT 61.105 71.320 61.335 71.380 ;
        RECT 35.760 70.190 36.330 71.320 ;
        RECT 48.355 70.190 48.925 71.320 ;
        RECT 60.940 70.190 61.510 71.320 ;
        RECT 35.945 70.130 36.175 70.190 ;
        RECT 48.525 70.130 48.755 70.190 ;
        RECT 61.105 70.130 61.335 70.190 ;
        RECT 36.225 69.695 42.185 69.925 ;
        RECT 42.515 69.695 48.475 69.925 ;
        RECT 48.805 69.695 54.765 69.925 ;
        RECT 55.095 69.695 61.055 69.925 ;
        RECT 38.585 67.925 39.865 69.695 ;
        RECT 44.865 67.925 46.145 69.695 ;
        RECT 51.140 67.925 52.420 69.695 ;
        RECT 57.425 67.925 58.705 69.695 ;
        RECT 73.335 68.950 73.715 73.080 ;
        RECT 77.915 68.950 78.295 73.080 ;
        RECT 94.040 72.990 94.270 73.050 ;
        RECT 93.965 70.610 94.345 72.990 ;
        RECT 94.040 70.550 94.270 70.610 ;
        RECT 96.545 70.345 96.925 73.255 ;
        RECT 99.125 70.345 99.505 73.255 ;
        RECT 101.780 72.990 102.010 73.050 ;
        RECT 101.705 70.610 102.085 72.990 ;
        RECT 106.770 71.905 107.080 73.190 ;
        RECT 107.410 71.905 107.720 73.190 ;
        RECT 108.050 71.905 108.360 73.190 ;
        RECT 108.690 71.905 109.000 73.190 ;
        RECT 113.490 71.905 113.800 73.235 ;
        RECT 114.130 71.905 114.440 73.235 ;
        RECT 114.770 71.905 115.080 73.235 ;
        RECT 115.410 71.905 115.720 73.235 ;
        RECT 106.490 71.640 106.720 71.700 ;
        RECT 107.770 71.640 108.000 71.700 ;
        RECT 109.050 71.640 109.280 71.700 ;
        RECT 113.850 71.640 114.080 71.700 ;
        RECT 115.130 71.640 115.360 71.700 ;
        RECT 106.415 70.880 106.795 71.640 ;
        RECT 107.695 70.880 108.075 71.640 ;
        RECT 108.975 70.880 109.355 71.640 ;
        RECT 113.785 70.880 114.145 71.640 ;
        RECT 115.065 70.880 115.425 71.640 ;
        RECT 106.490 70.820 106.720 70.880 ;
        RECT 107.770 70.820 108.000 70.880 ;
        RECT 109.050 70.820 109.280 70.880 ;
        RECT 113.850 70.820 114.080 70.880 ;
        RECT 115.130 70.820 115.360 70.880 ;
        RECT 101.780 70.550 102.010 70.610 ;
        RECT 93.030 70.115 103.020 70.345 ;
        RECT 106.770 69.345 107.080 70.615 ;
        RECT 107.410 69.345 107.720 70.615 ;
        RECT 108.050 69.340 108.360 70.615 ;
        RECT 108.690 69.345 109.000 70.615 ;
        RECT 113.490 69.300 113.800 70.615 ;
        RECT 114.130 69.300 114.440 70.615 ;
        RECT 114.770 69.300 115.080 70.615 ;
        RECT 115.410 69.300 115.720 70.615 ;
        RECT 73.410 68.890 73.640 68.950 ;
        RECT 77.990 68.890 78.220 68.950 ;
        RECT 72.080 68.685 72.720 68.730 ;
        RECT 74.360 68.685 75.000 68.730 ;
        RECT 76.610 68.685 77.250 68.730 ;
        RECT 78.925 68.685 79.565 68.730 ;
        RECT 71.400 68.455 73.360 68.685 ;
        RECT 73.690 68.455 75.650 68.685 ;
        RECT 75.980 68.455 77.940 68.685 ;
        RECT 78.270 68.455 80.230 68.685 ;
        RECT 72.080 68.360 72.720 68.455 ;
        RECT 74.360 68.360 75.000 68.455 ;
        RECT 76.610 68.360 77.250 68.455 ;
        RECT 78.925 68.360 79.565 68.455 ;
        RECT 36.225 67.695 42.185 67.925 ;
        RECT 42.515 67.695 48.475 67.925 ;
        RECT 48.805 67.695 54.765 67.925 ;
        RECT 55.095 67.695 61.055 67.925 ;
        RECT 35.945 67.430 36.175 67.490 ;
        RECT 48.525 67.430 48.755 67.490 ;
        RECT 61.105 67.430 61.335 67.490 ;
        RECT 35.760 66.300 36.330 67.430 ;
        RECT 48.355 66.300 48.925 67.430 ;
        RECT 60.950 66.300 61.520 67.430 ;
        RECT 106.890 66.755 110.400 66.985 ;
        RECT 107.250 66.535 107.480 66.595 ;
        RECT 35.945 66.240 36.175 66.300 ;
        RECT 48.525 66.240 48.755 66.300 ;
        RECT 61.105 66.240 61.335 66.300 ;
        RECT 36.225 65.805 42.185 66.035 ;
        RECT 42.515 65.805 48.475 66.035 ;
        RECT 48.805 65.805 54.765 66.035 ;
        RECT 55.095 65.805 61.055 66.035 ;
        RECT 72.615 65.950 73.255 66.005 ;
        RECT 74.900 65.950 75.540 66.020 ;
        RECT 77.185 65.950 77.825 66.020 ;
        RECT 79.460 65.950 80.100 66.020 ;
        RECT 81.755 65.950 82.395 66.020 ;
        RECT 84.060 65.950 84.700 66.020 ;
        RECT 38.585 64.035 39.865 65.805 ;
        RECT 44.865 64.035 46.145 65.805 ;
        RECT 51.140 64.035 52.420 65.805 ;
        RECT 57.425 64.035 58.705 65.805 ;
        RECT 71.955 65.720 73.915 65.950 ;
        RECT 74.245 65.720 76.205 65.950 ;
        RECT 76.535 65.720 78.495 65.950 ;
        RECT 78.825 65.720 80.785 65.950 ;
        RECT 81.115 65.720 83.075 65.950 ;
        RECT 83.405 65.720 85.365 65.950 ;
        RECT 72.615 65.635 73.255 65.720 ;
        RECT 74.900 65.650 75.540 65.720 ;
        RECT 77.185 65.650 77.825 65.720 ;
        RECT 79.460 65.650 80.100 65.720 ;
        RECT 81.755 65.650 82.395 65.720 ;
        RECT 84.060 65.650 84.700 65.720 ;
        RECT 71.675 65.455 71.905 65.515 ;
        RECT 73.965 65.455 74.195 65.515 ;
        RECT 76.255 65.455 76.485 65.515 ;
        RECT 78.545 65.455 78.775 65.515 ;
        RECT 80.835 65.455 81.065 65.515 ;
        RECT 83.125 65.455 83.355 65.515 ;
        RECT 85.415 65.455 85.645 65.515 ;
        RECT 36.225 63.805 42.185 64.035 ;
        RECT 42.515 63.805 48.475 64.035 ;
        RECT 48.805 63.805 54.765 64.035 ;
        RECT 55.095 63.805 61.055 64.035 ;
        RECT 35.945 63.540 36.175 63.600 ;
        RECT 48.525 63.540 48.755 63.600 ;
        RECT 61.105 63.540 61.335 63.600 ;
        RECT 35.760 62.410 36.330 63.540 ;
        RECT 48.355 62.410 48.925 63.540 ;
        RECT 60.945 62.410 61.515 63.540 ;
        RECT 35.945 62.350 36.175 62.410 ;
        RECT 48.525 62.350 48.755 62.410 ;
        RECT 61.105 62.350 61.335 62.410 ;
        RECT 36.225 61.915 42.185 62.145 ;
        RECT 42.515 61.915 48.475 62.145 ;
        RECT 48.805 61.915 54.765 62.145 ;
        RECT 55.095 61.915 61.055 62.145 ;
        RECT 38.585 61.355 39.865 61.915 ;
        RECT 44.865 61.355 46.145 61.915 ;
        RECT 51.140 61.355 52.420 61.915 ;
        RECT 57.420 61.520 58.705 61.915 ;
        RECT 57.425 61.355 58.705 61.520 ;
        RECT 71.600 61.325 71.980 65.455 ;
        RECT 73.890 61.325 74.270 65.455 ;
        RECT 76.180 61.325 76.560 65.455 ;
        RECT 78.470 61.325 78.850 65.455 ;
        RECT 80.760 61.325 81.140 65.455 ;
        RECT 83.050 61.325 83.430 65.455 ;
        RECT 85.340 61.325 85.720 65.455 ;
        RECT 97.660 64.640 98.300 66.250 ;
        RECT 98.950 64.640 99.590 66.360 ;
        RECT 97.500 64.410 98.460 64.640 ;
        RECT 98.790 64.410 99.750 64.640 ;
        RECT 95.930 64.190 96.160 64.250 ;
        RECT 97.220 64.190 97.450 64.250 ;
        RECT 98.510 64.190 98.740 64.250 ;
        RECT 95.855 63.060 96.235 64.190 ;
        RECT 97.145 63.060 97.525 64.190 ;
        RECT 98.435 63.060 98.815 64.190 ;
        RECT 99.800 64.185 100.030 64.250 ;
        RECT 101.090 64.190 101.320 64.250 ;
        RECT 95.930 63.000 96.160 63.060 ;
        RECT 97.220 63.000 97.450 63.060 ;
        RECT 98.510 63.000 98.740 63.060 ;
        RECT 99.725 63.055 100.105 64.185 ;
        RECT 101.015 63.060 101.395 64.190 ;
        RECT 107.175 63.155 107.555 66.535 ;
        RECT 107.250 63.095 107.480 63.155 ;
        RECT 99.800 63.000 100.030 63.055 ;
        RECT 101.090 63.000 101.320 63.060 ;
        RECT 108.455 62.935 108.835 66.755 ;
        RECT 109.810 66.570 110.040 66.595 ;
        RECT 109.735 63.190 110.115 66.570 ;
        RECT 114.650 65.560 114.940 66.895 ;
        RECT 115.610 65.560 115.900 66.895 ;
        RECT 116.570 65.560 116.860 66.895 ;
        RECT 117.530 65.560 117.820 66.895 ;
        RECT 118.490 65.560 118.780 66.895 ;
        RECT 119.450 65.560 119.740 66.895 ;
        RECT 120.410 65.560 120.700 66.895 ;
        RECT 121.370 65.560 121.660 66.895 ;
        RECT 122.330 65.560 122.620 66.895 ;
        RECT 123.290 65.560 123.580 66.895 ;
        RECT 124.250 65.560 124.540 66.895 ;
        RECT 125.210 65.560 125.500 66.895 ;
        RECT 126.170 65.560 126.460 66.895 ;
        RECT 127.130 65.560 127.420 66.895 ;
        RECT 128.090 65.560 128.380 66.895 ;
        RECT 129.050 65.560 129.340 66.895 ;
        RECT 130.010 65.560 130.300 66.895 ;
        RECT 130.970 65.560 131.260 66.895 ;
        RECT 131.930 65.560 132.220 66.895 ;
        RECT 132.890 65.560 133.180 66.895 ;
        RECT 133.850 65.560 134.140 66.895 ;
        RECT 134.810 65.560 135.100 66.895 ;
        RECT 135.770 65.560 136.060 66.895 ;
        RECT 136.730 65.560 137.020 66.895 ;
        RECT 137.690 65.560 137.980 66.895 ;
        RECT 109.810 63.095 110.040 63.190 ;
        RECT 97.500 62.610 98.460 62.840 ;
        RECT 98.790 62.610 99.750 62.840 ;
        RECT 106.890 62.705 110.400 62.935 ;
        RECT 71.675 61.265 71.905 61.325 ;
        RECT 73.965 61.265 74.195 61.325 ;
        RECT 76.255 61.265 76.485 61.325 ;
        RECT 78.545 61.265 78.775 61.325 ;
        RECT 80.835 61.265 81.065 61.325 ;
        RECT 83.125 61.265 83.355 61.325 ;
        RECT 85.415 61.265 85.645 61.325 ;
        RECT 72.605 61.060 73.245 61.100 ;
        RECT 74.900 61.060 75.540 61.100 ;
        RECT 77.180 61.060 77.820 61.100 ;
        RECT 79.455 61.060 80.095 61.100 ;
        RECT 81.755 61.060 82.395 61.100 ;
        RECT 84.065 61.060 84.705 61.100 ;
        RECT 71.955 60.830 73.915 61.060 ;
        RECT 74.245 60.830 76.205 61.060 ;
        RECT 76.535 60.830 78.495 61.060 ;
        RECT 78.825 60.830 80.785 61.060 ;
        RECT 81.115 60.830 83.075 61.060 ;
        RECT 83.405 60.830 85.365 61.060 ;
        RECT 97.660 60.995 98.300 62.610 ;
        RECT 98.950 60.995 99.590 62.610 ;
        RECT 72.605 60.730 73.245 60.830 ;
        RECT 74.900 60.730 75.540 60.830 ;
        RECT 77.180 60.730 77.820 60.830 ;
        RECT 79.455 60.730 80.095 60.830 ;
        RECT 81.755 60.730 82.395 60.830 ;
        RECT 84.065 60.730 84.705 60.830 ;
        RECT 144.520 60.455 144.750 63.580 ;
        RECT 144.505 59.815 144.765 60.455 ;
        RECT 144.520 56.980 144.750 59.815 ;
        RECT 145.150 57.860 145.380 63.580 ;
        RECT 145.780 63.415 146.010 63.580 ;
        RECT 145.765 62.775 146.025 63.415 ;
        RECT 145.135 57.220 145.395 57.860 ;
        RECT 145.150 56.980 145.380 57.220 ;
        RECT 145.780 56.980 146.010 62.775 ;
        RECT 146.410 57.860 146.640 63.580 ;
        RECT 147.040 60.455 147.270 63.580 ;
        RECT 147.025 59.815 147.285 60.455 ;
        RECT 146.395 57.220 146.655 57.860 ;
        RECT 146.410 56.980 146.640 57.220 ;
        RECT 147.040 56.980 147.270 59.815 ;
        RECT 34.900 55.550 36.180 56.110 ;
        RECT 37.110 55.550 38.390 56.110 ;
        RECT 39.995 55.550 41.275 56.110 ;
        RECT 42.875 55.550 44.155 56.110 ;
        RECT 45.145 55.550 46.425 56.110 ;
        RECT 47.925 55.550 49.205 56.110 ;
        RECT 50.855 55.550 52.135 56.110 ;
        RECT 53.130 55.550 54.410 56.110 ;
        RECT 34.515 55.320 36.475 55.550 ;
        RECT 36.805 55.320 38.765 55.550 ;
        RECT 39.655 55.320 41.615 55.550 ;
        RECT 42.505 55.320 44.465 55.550 ;
        RECT 44.795 55.320 46.755 55.550 ;
        RECT 47.645 55.320 49.605 55.550 ;
        RECT 50.495 55.320 52.455 55.550 ;
        RECT 52.785 55.320 54.745 55.550 ;
        RECT 60.400 55.485 61.040 56.555 ;
        RECT 61.680 55.485 62.320 56.555 ;
        RECT 62.980 55.485 63.620 56.555 ;
        RECT 64.265 55.485 64.905 56.555 ;
        RECT 65.535 55.485 66.175 56.555 ;
        RECT 66.840 55.485 67.480 56.555 ;
        RECT 68.135 56.540 68.775 56.555 ;
        RECT 69.425 56.540 70.065 56.555 ;
        RECT 68.115 56.210 68.775 56.540 ;
        RECT 69.400 56.210 70.065 56.540 ;
        RECT 68.135 55.485 68.775 56.210 ;
        RECT 69.425 55.485 70.065 56.210 ;
        RECT 78.535 55.705 78.785 55.765 ;
        RECT 60.235 55.255 61.195 55.485 ;
        RECT 61.525 55.255 62.485 55.485 ;
        RECT 62.815 55.255 63.775 55.485 ;
        RECT 64.105 55.255 65.065 55.485 ;
        RECT 65.395 55.255 66.355 55.485 ;
        RECT 66.685 55.255 67.645 55.485 ;
        RECT 67.975 55.255 68.935 55.485 ;
        RECT 69.265 55.255 70.225 55.485 ;
        RECT 36.525 55.055 36.755 55.115 ;
        RECT 39.375 55.055 39.605 55.115 ;
        RECT 44.515 55.055 44.745 55.115 ;
        RECT 47.365 55.055 47.595 55.115 ;
        RECT 52.505 55.055 52.735 55.115 ;
        RECT 36.450 53.675 36.830 55.055 ;
        RECT 39.300 53.675 39.680 55.055 ;
        RECT 44.440 53.675 44.820 55.055 ;
        RECT 47.290 53.675 47.670 55.055 ;
        RECT 52.430 53.675 52.810 55.055 ;
        RECT 78.470 53.720 78.850 55.705 ;
        RECT 36.525 53.615 36.755 53.675 ;
        RECT 39.375 53.615 39.605 53.675 ;
        RECT 44.515 53.615 44.745 53.675 ;
        RECT 47.365 53.615 47.595 53.675 ;
        RECT 52.505 53.615 52.735 53.675 ;
        RECT 78.535 53.660 78.785 53.720 ;
        RECT 79.365 53.660 80.445 55.765 ;
        RECT 81.025 53.660 82.105 55.765 ;
        RECT 85.825 53.660 86.905 55.765 ;
        RECT 87.485 53.660 88.565 55.765 ;
        RECT 91.455 55.700 91.705 55.765 ;
        RECT 91.390 53.715 91.770 55.700 ;
        RECT 91.455 53.660 91.705 53.715 ;
        RECT 92.285 53.660 93.365 55.765 ;
        RECT 93.945 53.660 95.025 55.765 ;
        RECT 95.605 53.660 96.685 55.765 ;
        RECT 97.265 53.660 98.345 55.765 ;
        RECT 98.925 55.705 99.175 55.765 ;
        RECT 102.065 55.745 102.315 55.765 ;
        RECT 105.205 55.755 105.455 55.765 ;
        RECT 98.860 53.720 99.240 55.705 ;
        RECT 98.925 53.660 99.175 53.720 ;
        RECT 101.980 53.680 102.400 55.745 ;
        RECT 105.125 53.690 105.545 55.755 ;
        RECT 162.575 54.255 162.905 54.945 ;
        RECT 163.525 54.255 163.855 54.525 ;
        RECT 164.475 54.255 164.805 54.525 ;
        RECT 165.425 54.255 165.755 54.945 ;
        RECT 102.065 53.660 102.315 53.680 ;
        RECT 105.205 53.660 105.455 53.690 ;
        RECT 34.515 53.180 36.475 53.410 ;
        RECT 36.805 53.180 38.765 53.410 ;
        RECT 39.655 53.180 41.615 53.410 ;
        RECT 42.505 53.180 44.465 53.410 ;
        RECT 44.795 53.180 46.755 53.410 ;
        RECT 47.645 53.180 49.605 53.410 ;
        RECT 50.495 53.180 52.455 53.410 ;
        RECT 52.785 53.180 54.745 53.410 ;
        RECT 60.235 53.365 61.195 53.595 ;
        RECT 61.525 53.365 62.485 53.595 ;
        RECT 62.815 53.365 63.775 53.595 ;
        RECT 64.105 53.365 65.065 53.595 ;
        RECT 65.395 53.365 66.355 53.595 ;
        RECT 66.685 53.365 67.645 53.595 ;
        RECT 67.975 53.365 68.935 53.595 ;
        RECT 69.265 53.365 70.225 53.595 ;
        RECT 144.590 53.450 144.910 53.710 ;
        RECT 148.740 53.555 148.970 53.610 ;
        RECT 162.410 53.560 162.640 54.065 ;
        RECT 34.900 52.620 36.180 53.180 ;
        RECT 37.110 52.620 38.390 53.180 ;
        RECT 39.995 52.620 41.275 53.180 ;
        RECT 42.875 52.620 44.155 53.180 ;
        RECT 45.145 52.620 46.425 53.180 ;
        RECT 47.925 52.620 49.205 53.180 ;
        RECT 50.855 52.620 52.135 53.180 ;
        RECT 53.130 52.620 54.410 53.180 ;
        RECT 60.400 52.295 61.040 53.365 ;
        RECT 61.680 52.295 62.320 53.365 ;
        RECT 62.980 52.295 63.620 53.365 ;
        RECT 64.265 52.295 64.905 53.365 ;
        RECT 65.535 52.295 66.175 53.365 ;
        RECT 66.840 52.295 67.480 53.365 ;
        RECT 68.135 52.295 68.775 53.365 ;
        RECT 69.425 52.295 70.065 53.365 ;
        RECT 144.615 53.160 144.845 53.450 ;
        RECT 148.725 53.235 148.985 53.555 ;
        RECT 162.395 53.240 162.655 53.560 ;
        RECT 148.740 53.190 148.970 53.235 ;
        RECT 162.410 51.565 162.640 53.240 ;
        RECT 163.360 51.900 163.590 54.065 ;
        RECT 164.310 51.900 164.540 54.065 ;
        RECT 165.260 53.560 165.490 54.065 ;
        RECT 165.245 53.240 165.505 53.560 ;
        RECT 163.345 51.570 163.605 51.900 ;
        RECT 164.295 51.570 164.555 51.900 ;
        RECT 163.360 51.565 163.590 51.570 ;
        RECT 164.310 51.565 164.540 51.570 ;
        RECT 165.260 51.565 165.490 53.240 ;
        RECT 162.575 50.665 162.905 51.375 ;
        RECT 163.525 51.105 163.855 51.375 ;
        RECT 164.475 51.105 164.805 51.375 ;
        RECT 165.425 50.665 165.755 51.375 ;
        RECT 91.455 48.345 92.535 50.450 ;
        RECT 93.115 48.345 94.195 50.450 ;
        RECT 94.775 48.345 95.855 50.450 ;
        RECT 96.435 48.345 97.515 50.450 ;
        RECT 98.095 48.345 99.175 50.450 ;
        RECT 143.625 49.720 143.975 49.990 ;
        RECT 145.935 49.720 146.285 49.990 ;
        RECT 150.110 48.830 150.460 49.545 ;
        RECT 150.740 48.830 151.090 49.100 ;
        RECT 151.370 48.830 151.720 49.100 ;
        RECT 152.000 48.830 152.350 49.545 ;
        RECT 143.625 48.520 143.975 48.790 ;
        RECT 145.935 48.520 146.285 48.790 ;
        RECT 149.855 47.910 150.085 48.640 ;
        RECT 150.470 48.370 150.730 48.690 ;
        RECT 149.840 47.590 150.100 47.910 ;
        RECT 150.485 47.640 150.715 48.370 ;
        RECT 151.115 48.285 151.345 48.640 ;
        RECT 151.730 48.350 151.990 48.670 ;
        RECT 151.100 47.965 151.360 48.285 ;
        RECT 151.115 47.640 151.345 47.965 ;
        RECT 151.745 47.640 151.975 48.350 ;
        RECT 152.375 47.880 152.605 48.640 ;
        RECT 152.330 47.620 152.650 47.880 ;
        RECT 143.700 46.625 144.030 46.895 ;
        RECT 145.790 46.625 146.120 46.895 ;
        RECT 150.110 46.735 150.460 47.450 ;
        RECT 150.740 47.180 151.090 47.450 ;
        RECT 151.370 47.180 151.720 47.450 ;
        RECT 152.000 46.780 152.350 47.450 ;
        RECT 35.705 45.520 36.345 46.080 ;
        RECT 38.010 45.520 38.650 46.080 ;
        RECT 40.300 45.520 40.940 46.090 ;
        RECT 42.585 45.520 43.225 46.080 ;
        RECT 56.805 45.520 57.445 46.085 ;
        RECT 59.090 45.520 59.730 46.085 ;
        RECT 61.380 45.520 62.020 46.085 ;
        RECT 63.655 45.520 64.295 46.085 ;
        RECT 65.955 45.520 66.595 46.085 ;
        RECT 68.240 45.520 68.880 46.085 ;
        RECT 35.045 45.290 37.005 45.520 ;
        RECT 37.335 45.290 39.295 45.520 ;
        RECT 39.625 45.290 41.585 45.520 ;
        RECT 41.915 45.290 43.875 45.520 ;
        RECT 56.135 45.290 58.095 45.520 ;
        RECT 58.425 45.290 60.385 45.520 ;
        RECT 60.715 45.290 62.675 45.520 ;
        RECT 63.005 45.290 64.965 45.520 ;
        RECT 65.295 45.290 67.255 45.520 ;
        RECT 67.585 45.290 69.545 45.520 ;
        RECT 34.765 45.025 34.995 45.130 ;
        RECT 39.345 45.025 39.575 45.130 ;
        RECT 43.925 45.025 44.155 45.130 ;
        RECT 34.645 42.750 35.115 45.025 ;
        RECT 39.225 42.750 39.695 45.025 ;
        RECT 43.810 42.750 44.280 45.025 ;
        RECT 34.765 42.630 34.995 42.750 ;
        RECT 39.345 42.630 39.575 42.750 ;
        RECT 43.925 42.630 44.155 42.750 ;
        RECT 58.025 42.630 58.495 45.130 ;
        RECT 62.600 42.630 63.070 45.130 ;
        RECT 67.185 42.630 67.655 45.130 ;
        RECT 78.535 42.915 79.615 45.020 ;
        RECT 80.195 42.915 81.275 45.020 ;
        RECT 84.995 42.915 86.075 45.020 ;
        RECT 86.655 42.915 87.735 45.020 ;
        RECT 88.315 44.960 88.565 45.020 ;
        RECT 88.250 42.975 88.630 44.960 ;
        RECT 161.060 43.855 161.290 44.510 ;
        RECT 161.045 43.525 161.305 43.855 ;
        RECT 88.315 42.915 88.565 42.975 ;
        RECT 35.045 42.240 37.005 42.470 ;
        RECT 37.335 42.240 39.295 42.470 ;
        RECT 39.625 42.240 41.585 42.470 ;
        RECT 41.915 42.240 43.875 42.470 ;
        RECT 56.135 42.240 58.095 42.470 ;
        RECT 58.425 42.240 60.385 42.470 ;
        RECT 60.715 42.240 62.675 42.470 ;
        RECT 63.005 42.240 64.965 42.470 ;
        RECT 65.295 42.240 67.255 42.470 ;
        RECT 67.585 42.240 69.545 42.470 ;
        RECT 35.705 40.470 36.345 42.240 ;
        RECT 38.010 40.470 38.650 42.240 ;
        RECT 40.300 40.470 40.940 42.240 ;
        RECT 42.585 40.470 43.225 42.240 ;
        RECT 56.805 40.470 57.445 42.240 ;
        RECT 59.090 40.470 59.730 42.240 ;
        RECT 61.380 40.470 62.020 42.240 ;
        RECT 63.655 40.470 64.295 42.240 ;
        RECT 65.955 40.470 66.595 42.240 ;
        RECT 68.240 40.470 68.880 42.240 ;
        RECT 151.105 42.035 151.335 42.325 ;
        RECT 153.665 42.035 153.895 42.325 ;
        RECT 151.060 41.775 151.380 42.035 ;
        RECT 153.620 41.775 153.940 42.035 ;
        RECT 161.060 42.010 161.290 43.525 ;
        RECT 162.010 43.085 162.240 44.510 ;
        RECT 162.960 43.085 163.190 44.510 ;
        RECT 163.910 43.855 164.140 44.510 ;
        RECT 164.860 43.855 165.090 44.510 ;
        RECT 163.895 43.525 164.155 43.855 ;
        RECT 164.845 43.525 165.105 43.855 ;
        RECT 161.995 42.755 162.255 43.085 ;
        RECT 162.945 42.755 163.205 43.085 ;
        RECT 162.010 42.010 162.240 42.755 ;
        RECT 162.960 42.010 163.190 42.755 ;
        RECT 163.910 42.010 164.140 43.525 ;
        RECT 164.860 42.010 165.090 43.525 ;
        RECT 165.810 43.085 166.040 44.510 ;
        RECT 166.760 43.085 166.990 44.510 ;
        RECT 167.710 43.855 167.940 44.510 ;
        RECT 167.695 43.525 167.955 43.855 ;
        RECT 165.795 42.755 166.055 43.085 ;
        RECT 166.745 42.755 167.005 43.085 ;
        RECT 165.810 42.010 166.040 42.755 ;
        RECT 166.760 42.010 166.990 42.755 ;
        RECT 167.710 42.010 167.940 43.525 ;
        RECT 143.700 40.975 144.030 41.245 ;
        RECT 145.790 41.240 146.120 41.245 ;
        RECT 145.790 40.980 146.135 41.240 ;
        RECT 145.790 40.975 146.120 40.980 ;
        RECT 35.045 40.240 37.005 40.470 ;
        RECT 37.335 40.240 39.295 40.470 ;
        RECT 39.625 40.240 41.585 40.470 ;
        RECT 41.915 40.240 43.875 40.470 ;
        RECT 56.135 40.240 58.095 40.470 ;
        RECT 58.425 40.240 60.385 40.470 ;
        RECT 60.715 40.240 62.675 40.470 ;
        RECT 63.005 40.240 64.965 40.470 ;
        RECT 65.295 40.240 67.255 40.470 ;
        RECT 67.585 40.240 69.545 40.470 ;
        RECT 34.765 39.965 34.995 40.080 ;
        RECT 39.345 39.970 39.575 40.080 ;
        RECT 43.925 39.970 44.155 40.080 ;
        RECT 34.645 37.690 35.115 39.965 ;
        RECT 39.225 37.695 39.695 39.970 ;
        RECT 43.810 37.695 44.280 39.970 ;
        RECT 34.765 37.580 34.995 37.690 ;
        RECT 39.345 37.580 39.575 37.695 ;
        RECT 43.925 37.580 44.155 37.695 ;
        RECT 58.025 37.580 58.495 40.080 ;
        RECT 62.595 37.740 63.080 40.080 ;
        RECT 67.170 37.740 67.655 40.080 ;
        RECT 161.060 39.585 161.290 40.240 ;
        RECT 78.920 38.700 79.560 39.260 ;
        RECT 80.190 38.700 80.830 39.260 ;
        RECT 161.045 39.255 161.305 39.585 ;
        RECT 78.745 38.470 79.705 38.700 ;
        RECT 80.035 38.470 80.995 38.700 ;
        RECT 78.465 38.250 78.695 38.310 ;
        RECT 81.045 38.250 81.275 38.310 ;
        RECT 78.390 37.870 78.770 38.250 ;
        RECT 80.970 37.870 81.350 38.250 ;
        RECT 78.465 37.810 78.695 37.870 ;
        RECT 81.045 37.810 81.275 37.870 ;
        RECT 161.060 37.740 161.290 39.255 ;
        RECT 162.010 38.815 162.240 40.240 ;
        RECT 162.960 38.815 163.190 40.240 ;
        RECT 163.910 39.585 164.140 40.240 ;
        RECT 164.860 39.585 165.090 40.240 ;
        RECT 163.895 39.255 164.155 39.585 ;
        RECT 164.845 39.255 165.105 39.585 ;
        RECT 161.995 38.485 162.255 38.815 ;
        RECT 162.945 38.485 163.205 38.815 ;
        RECT 162.010 37.740 162.240 38.485 ;
        RECT 162.960 37.740 163.190 38.485 ;
        RECT 163.910 37.740 164.140 39.255 ;
        RECT 164.860 37.740 165.090 39.255 ;
        RECT 165.810 38.815 166.040 40.240 ;
        RECT 166.760 38.815 166.990 40.240 ;
        RECT 167.710 39.585 167.940 40.240 ;
        RECT 167.695 39.255 167.955 39.585 ;
        RECT 165.795 38.485 166.055 38.815 ;
        RECT 166.745 38.485 167.005 38.815 ;
        RECT 165.810 37.740 166.040 38.485 ;
        RECT 166.760 37.740 166.990 38.485 ;
        RECT 167.710 37.740 167.940 39.255 ;
        RECT 62.725 37.580 62.955 37.740 ;
        RECT 67.305 37.580 67.535 37.740 ;
        RECT 78.745 37.420 79.705 37.650 ;
        RECT 80.035 37.420 80.995 37.650 ;
        RECT 35.045 37.190 37.005 37.420 ;
        RECT 37.335 37.190 39.295 37.420 ;
        RECT 39.625 37.190 41.585 37.420 ;
        RECT 41.915 37.190 43.875 37.420 ;
        RECT 56.135 37.190 58.095 37.420 ;
        RECT 58.425 37.190 60.385 37.420 ;
        RECT 60.715 37.190 62.675 37.420 ;
        RECT 63.005 37.190 64.965 37.420 ;
        RECT 65.295 37.190 67.255 37.420 ;
        RECT 67.585 37.190 69.545 37.420 ;
        RECT 35.705 35.420 36.345 37.190 ;
        RECT 38.010 35.420 38.650 37.190 ;
        RECT 40.300 35.420 40.940 37.190 ;
        RECT 42.585 35.420 43.225 37.190 ;
        RECT 56.805 35.420 57.445 37.190 ;
        RECT 59.090 35.420 59.730 37.190 ;
        RECT 61.380 35.420 62.020 37.190 ;
        RECT 63.655 35.420 64.295 37.190 ;
        RECT 65.955 35.420 66.595 37.190 ;
        RECT 68.240 35.420 68.880 37.190 ;
        RECT 78.920 36.860 79.560 37.420 ;
        RECT 80.190 36.860 80.830 37.420 ;
        RECT 35.045 35.190 37.005 35.420 ;
        RECT 37.335 35.190 39.295 35.420 ;
        RECT 39.625 35.190 41.585 35.420 ;
        RECT 41.915 35.190 43.875 35.420 ;
        RECT 56.135 35.190 58.095 35.420 ;
        RECT 58.425 35.190 60.385 35.420 ;
        RECT 60.715 35.190 62.675 35.420 ;
        RECT 63.005 35.190 64.965 35.420 ;
        RECT 65.295 35.190 67.255 35.420 ;
        RECT 67.585 35.190 69.545 35.420 ;
        RECT 34.765 34.900 34.995 35.030 ;
        RECT 39.345 34.900 39.575 35.030 ;
        RECT 43.925 34.900 44.155 35.030 ;
        RECT 58.145 34.970 58.375 35.030 ;
        RECT 62.725 34.970 62.955 35.030 ;
        RECT 67.305 34.970 67.535 35.030 ;
        RECT 34.645 32.625 35.115 34.900 ;
        RECT 39.225 32.625 39.695 34.900 ;
        RECT 43.810 32.625 44.280 34.900 ;
        RECT 58.020 32.630 58.505 34.970 ;
        RECT 62.600 32.630 63.085 34.970 ;
        RECT 67.175 32.630 67.660 34.970 ;
        RECT 78.250 34.240 78.890 35.310 ;
        RECT 79.550 34.240 80.190 35.310 ;
        RECT 80.820 34.240 81.460 35.310 ;
        RECT 82.110 34.240 82.750 35.310 ;
        RECT 78.090 34.010 79.050 34.240 ;
        RECT 79.380 34.010 80.340 34.240 ;
        RECT 80.670 34.010 81.630 34.240 ;
        RECT 81.960 34.010 82.920 34.240 ;
        RECT 79.100 33.790 79.330 33.850 ;
        RECT 81.680 33.790 81.910 33.850 ;
        RECT 79.025 32.660 79.405 33.790 ;
        RECT 81.605 32.660 81.985 33.790 ;
        RECT 34.765 32.530 34.995 32.625 ;
        RECT 39.345 32.530 39.575 32.625 ;
        RECT 43.925 32.530 44.155 32.625 ;
        RECT 58.145 32.530 58.375 32.630 ;
        RECT 62.725 32.530 62.955 32.630 ;
        RECT 67.305 32.530 67.535 32.630 ;
        RECT 79.100 32.600 79.330 32.660 ;
        RECT 81.680 32.600 81.910 32.660 ;
        RECT 35.045 32.140 37.005 32.370 ;
        RECT 37.335 32.140 39.295 32.370 ;
        RECT 39.625 32.140 41.585 32.370 ;
        RECT 41.915 32.140 43.875 32.370 ;
        RECT 56.135 32.140 58.095 32.370 ;
        RECT 58.425 32.140 60.385 32.370 ;
        RECT 60.715 32.140 62.675 32.370 ;
        RECT 63.005 32.140 64.965 32.370 ;
        RECT 65.295 32.140 67.255 32.370 ;
        RECT 67.585 32.140 69.545 32.370 ;
        RECT 78.090 32.210 79.050 32.440 ;
        RECT 79.380 32.210 80.340 32.440 ;
        RECT 80.670 32.210 81.630 32.440 ;
        RECT 81.960 32.210 82.920 32.440 ;
        RECT 35.705 31.580 36.345 32.140 ;
        RECT 38.010 31.580 38.650 32.140 ;
        RECT 40.300 31.580 40.940 32.140 ;
        RECT 42.585 31.580 43.225 32.140 ;
        RECT 56.805 31.580 57.445 32.140 ;
        RECT 59.090 31.580 59.730 32.140 ;
        RECT 61.380 31.580 62.020 32.140 ;
        RECT 63.655 31.580 64.295 32.140 ;
        RECT 65.955 31.580 66.595 32.140 ;
        RECT 68.240 31.580 68.880 32.140 ;
        RECT 78.250 31.140 78.890 32.210 ;
        RECT 79.550 31.140 80.190 32.210 ;
        RECT 80.820 31.140 81.460 32.210 ;
        RECT 82.110 31.140 82.750 32.210 ;
        RECT 79.370 29.700 81.610 29.930 ;
        RECT 79.370 29.480 79.600 29.700 ;
        RECT 79.295 28.600 79.675 29.480 ;
        RECT 115.130 28.990 115.420 29.150 ;
        RECT 116.090 28.990 116.380 29.150 ;
        RECT 117.050 28.990 117.340 29.150 ;
        RECT 115.125 28.920 115.420 28.990 ;
        RECT 116.085 28.920 116.380 28.990 ;
        RECT 117.045 28.920 117.340 28.990 ;
        RECT 79.370 28.380 79.600 28.600 ;
        RECT 79.370 28.150 81.610 28.380 ;
        RECT 115.125 27.815 115.415 28.920 ;
        RECT 116.085 27.815 116.375 28.920 ;
        RECT 117.045 27.815 117.335 28.920 ;
        RECT 118.010 27.815 118.300 29.150 ;
        RECT 118.970 27.815 119.260 29.150 ;
        RECT 119.930 27.815 120.220 29.150 ;
        RECT 120.890 27.815 121.180 29.150 ;
        RECT 121.850 27.815 122.140 29.150 ;
        RECT 122.810 27.815 123.100 29.150 ;
        RECT 123.770 27.815 124.060 29.150 ;
        RECT 124.730 27.815 125.020 29.150 ;
        RECT 125.690 27.815 125.980 29.150 ;
        RECT 126.650 28.190 126.940 29.150 ;
        RECT 127.610 28.190 127.900 29.150 ;
        RECT 128.570 28.190 128.860 29.150 ;
        RECT 129.530 28.190 129.820 29.150 ;
        RECT 130.490 28.190 130.780 29.150 ;
        RECT 131.450 28.190 131.740 29.150 ;
        RECT 126.650 27.875 126.945 28.190 ;
        RECT 127.610 27.875 127.905 28.190 ;
        RECT 128.570 27.875 128.865 28.190 ;
        RECT 126.655 27.815 126.945 27.875 ;
        RECT 127.615 27.815 127.905 27.875 ;
        RECT 128.575 27.815 128.865 27.875 ;
        RECT 129.530 27.855 129.825 28.190 ;
        RECT 130.490 27.855 130.785 28.190 ;
        RECT 131.450 27.855 131.745 28.190 ;
        RECT 129.535 27.815 129.825 27.855 ;
        RECT 130.495 27.815 130.785 27.855 ;
        RECT 131.455 27.815 131.745 27.855 ;
        RECT 132.410 27.815 132.700 29.150 ;
        RECT 133.370 27.815 133.660 29.150 ;
        RECT 134.330 27.815 134.620 29.150 ;
        RECT 135.290 28.190 135.580 29.150 ;
        RECT 136.250 28.190 136.540 29.150 ;
        RECT 137.210 28.190 137.500 29.150 ;
        RECT 138.170 28.190 138.460 29.150 ;
        RECT 135.290 27.855 135.585 28.190 ;
        RECT 136.250 27.855 136.545 28.190 ;
        RECT 135.295 27.815 135.585 27.855 ;
        RECT 136.255 27.815 136.545 27.855 ;
        RECT 137.210 27.815 137.505 28.190 ;
        RECT 138.170 27.815 138.465 28.190 ;
        RECT 36.720 24.460 43.035 24.690 ;
        RECT 56.205 24.460 62.165 24.690 ;
        RECT 62.495 24.460 68.455 24.690 ;
        RECT 68.785 24.460 74.745 24.690 ;
        RECT 75.075 24.460 81.035 24.690 ;
        RECT 36.720 14.360 37.100 24.460 ;
        RECT 57.760 24.410 60.540 24.460 ;
        RECT 64.195 24.410 66.975 24.460 ;
        RECT 70.465 24.410 73.245 24.460 ;
        RECT 76.510 24.410 79.290 24.460 ;
        RECT 55.925 24.240 56.155 24.300 ;
        RECT 62.215 24.240 62.445 24.300 ;
        RECT 68.505 24.240 68.735 24.300 ;
        RECT 74.795 24.240 75.025 24.300 ;
        RECT 81.085 24.240 81.315 24.300 ;
        RECT 36.795 14.300 37.025 14.360 ;
        RECT 55.850 14.355 56.230 24.240 ;
        RECT 62.140 14.360 62.520 24.240 ;
        RECT 68.430 14.360 68.810 24.240 ;
        RECT 74.720 14.360 75.100 24.240 ;
        RECT 81.010 14.360 81.390 24.240 ;
        RECT 93.525 23.740 94.305 23.760 ;
        RECT 95.815 23.740 96.595 23.745 ;
        RECT 98.105 23.740 98.885 23.745 ;
        RECT 100.395 23.740 101.175 23.745 ;
        RECT 102.685 23.740 103.465 23.745 ;
        RECT 104.975 23.740 105.755 23.745 ;
        RECT 107.265 23.740 108.045 23.745 ;
        RECT 109.555 23.740 110.335 23.745 ;
        RECT 111.845 23.740 112.625 23.745 ;
        RECT 114.135 23.740 114.915 23.745 ;
        RECT 116.425 23.740 117.205 23.745 ;
        RECT 118.715 23.740 119.495 23.745 ;
        RECT 121.005 23.740 121.785 23.745 ;
        RECT 123.295 23.740 124.075 23.745 ;
        RECT 92.935 23.510 94.895 23.740 ;
        RECT 95.225 23.510 97.185 23.740 ;
        RECT 97.515 23.510 99.475 23.740 ;
        RECT 99.805 23.510 101.765 23.740 ;
        RECT 102.095 23.510 104.055 23.740 ;
        RECT 104.385 23.510 106.345 23.740 ;
        RECT 106.675 23.510 108.635 23.740 ;
        RECT 108.965 23.510 110.925 23.740 ;
        RECT 111.255 23.510 113.215 23.740 ;
        RECT 113.545 23.510 115.505 23.740 ;
        RECT 115.835 23.510 117.795 23.740 ;
        RECT 118.125 23.510 120.085 23.740 ;
        RECT 120.415 23.510 122.375 23.740 ;
        RECT 122.705 23.510 124.665 23.740 ;
        RECT 93.525 23.480 94.305 23.510 ;
        RECT 95.815 23.465 96.595 23.510 ;
        RECT 98.105 23.465 98.885 23.510 ;
        RECT 100.395 23.465 101.175 23.510 ;
        RECT 102.685 23.465 103.465 23.510 ;
        RECT 104.975 23.465 105.755 23.510 ;
        RECT 107.265 23.465 108.045 23.510 ;
        RECT 109.555 23.465 110.335 23.510 ;
        RECT 111.845 23.465 112.625 23.510 ;
        RECT 114.135 23.465 114.915 23.510 ;
        RECT 116.425 23.465 117.205 23.510 ;
        RECT 118.715 23.465 119.495 23.510 ;
        RECT 121.005 23.465 121.785 23.510 ;
        RECT 123.295 23.465 124.075 23.510 ;
        RECT 94.945 23.285 95.175 23.350 ;
        RECT 99.525 23.285 99.755 23.350 ;
        RECT 104.105 23.285 104.335 23.350 ;
        RECT 108.685 23.285 108.915 23.350 ;
        RECT 113.265 23.285 113.495 23.350 ;
        RECT 117.845 23.285 118.075 23.350 ;
        RECT 122.425 23.285 122.655 23.350 ;
        RECT 94.870 22.160 95.250 23.285 ;
        RECT 99.450 22.160 99.830 23.285 ;
        RECT 104.030 22.160 104.410 23.285 ;
        RECT 108.610 22.160 108.990 23.285 ;
        RECT 113.190 22.160 113.570 23.285 ;
        RECT 117.770 22.160 118.150 23.285 ;
        RECT 122.350 22.160 122.730 23.285 ;
        RECT 94.945 22.100 95.175 22.160 ;
        RECT 99.525 22.100 99.755 22.160 ;
        RECT 104.105 22.100 104.335 22.160 ;
        RECT 108.685 22.100 108.915 22.160 ;
        RECT 113.265 22.100 113.495 22.160 ;
        RECT 117.845 22.100 118.075 22.160 ;
        RECT 122.425 22.100 122.655 22.160 ;
        RECT 93.525 21.940 94.305 21.985 ;
        RECT 95.815 21.940 96.595 21.985 ;
        RECT 98.105 21.940 98.885 21.985 ;
        RECT 100.395 21.940 101.175 21.985 ;
        RECT 102.685 21.940 103.465 21.985 ;
        RECT 104.975 21.940 105.755 21.985 ;
        RECT 107.265 21.940 108.045 21.985 ;
        RECT 109.555 21.940 110.335 21.985 ;
        RECT 111.845 21.940 112.625 21.985 ;
        RECT 114.130 21.940 114.910 21.985 ;
        RECT 116.425 21.940 117.205 21.985 ;
        RECT 118.715 21.940 119.495 21.985 ;
        RECT 121.005 21.940 121.785 21.985 ;
        RECT 123.295 21.940 124.075 21.985 ;
        RECT 92.935 21.710 94.895 21.940 ;
        RECT 95.225 21.710 97.185 21.940 ;
        RECT 97.515 21.710 99.475 21.940 ;
        RECT 99.805 21.710 101.765 21.940 ;
        RECT 102.095 21.710 104.055 21.940 ;
        RECT 104.385 21.710 106.345 21.940 ;
        RECT 106.675 21.710 108.635 21.940 ;
        RECT 108.965 21.710 110.925 21.940 ;
        RECT 111.255 21.710 113.215 21.940 ;
        RECT 113.545 21.710 115.505 21.940 ;
        RECT 115.835 21.710 117.795 21.940 ;
        RECT 118.125 21.710 120.085 21.940 ;
        RECT 120.415 21.710 122.375 21.940 ;
        RECT 122.705 21.710 124.665 21.940 ;
        RECT 93.525 21.705 94.305 21.710 ;
        RECT 95.815 21.705 96.595 21.710 ;
        RECT 98.105 21.705 98.885 21.710 ;
        RECT 100.395 21.705 101.175 21.710 ;
        RECT 102.685 21.705 103.465 21.710 ;
        RECT 104.975 21.705 105.755 21.710 ;
        RECT 107.265 21.705 108.045 21.710 ;
        RECT 109.555 21.705 110.335 21.710 ;
        RECT 111.845 21.705 112.625 21.710 ;
        RECT 114.130 21.705 114.910 21.710 ;
        RECT 116.425 21.705 117.205 21.710 ;
        RECT 118.715 21.705 119.495 21.710 ;
        RECT 121.005 21.705 121.785 21.710 ;
        RECT 123.295 21.705 124.075 21.710 ;
        RECT 55.925 14.300 56.155 14.355 ;
        RECT 62.215 14.300 62.445 14.360 ;
        RECT 68.505 14.300 68.735 14.360 ;
        RECT 74.795 14.300 75.025 14.360 ;
        RECT 81.085 14.300 81.315 14.360 ;
        RECT 37.075 13.910 43.035 14.140 ;
        RECT 56.205 13.910 62.165 14.140 ;
        RECT 62.495 13.910 68.455 14.140 ;
        RECT 68.785 13.910 74.745 14.140 ;
        RECT 75.075 13.910 81.035 14.140 ;
      LAYER met2 ;
        RECT 67.515 74.300 79.630 74.670 ;
        RECT 67.515 73.900 67.885 74.300 ;
        RECT 29.475 73.025 49.030 73.395 ;
        RECT 72.010 73.280 72.780 73.650 ;
        RECT 74.295 73.280 75.065 73.650 ;
        RECT 76.540 73.280 77.310 73.650 ;
        RECT 78.860 73.280 79.630 73.650 ;
        RECT 113.600 73.375 115.650 73.745 ;
        RECT 104.045 73.165 109.040 73.190 ;
        RECT 29.475 72.625 29.845 73.025 ;
        RECT 66.840 72.375 67.210 72.775 ;
        RECT 30.145 72.005 67.215 72.375 ;
        RECT 30.145 71.605 30.515 72.005 ;
        RECT 35.810 70.140 36.280 71.370 ;
        RECT 48.405 70.140 48.875 71.370 ;
        RECT 60.990 70.140 61.460 71.370 ;
        RECT 66.840 68.995 67.210 69.395 ;
        RECT 30.145 68.625 67.215 68.995 ;
        RECT 73.385 68.900 73.665 73.130 ;
        RECT 77.965 68.900 78.245 73.130 ;
        RECT 94.015 70.560 94.295 73.040 ;
        RECT 96.595 70.560 96.875 73.040 ;
        RECT 99.175 70.560 99.455 73.040 ;
        RECT 101.755 70.560 102.035 73.040 ;
        RECT 104.040 72.820 109.040 73.165 ;
        RECT 111.350 72.865 115.720 73.235 ;
        RECT 104.040 72.420 104.420 72.820 ;
        RECT 111.355 72.465 111.725 72.865 ;
        RECT 106.465 70.830 106.745 71.700 ;
        RECT 107.745 70.830 108.025 71.690 ;
        RECT 109.025 70.830 109.305 71.700 ;
        RECT 113.825 70.830 114.105 71.690 ;
        RECT 115.105 70.830 115.385 71.690 ;
        RECT 104.045 70.090 104.415 70.115 ;
        RECT 104.040 69.715 104.420 70.090 ;
        RECT 96.545 69.030 99.285 69.400 ;
        RECT 104.040 69.345 109.040 69.715 ;
        RECT 111.350 69.300 115.720 69.670 ;
        RECT 111.350 69.205 111.730 69.300 ;
        RECT 104.720 68.835 111.730 69.205 ;
        RECT 30.145 68.225 30.515 68.625 ;
        RECT 30.885 68.115 61.585 68.485 ;
        RECT 72.010 68.360 72.780 68.730 ;
        RECT 74.295 68.360 75.065 68.730 ;
        RECT 76.540 68.360 77.310 68.730 ;
        RECT 78.860 68.360 79.630 68.730 ;
        RECT 93.945 68.430 104.420 68.800 ;
        RECT 104.720 68.440 105.100 68.835 ;
        RECT 111.870 68.790 115.630 69.160 ;
        RECT 111.870 68.695 112.240 68.790 ;
        RECT 104.725 68.435 105.095 68.440 ;
        RECT 30.885 67.715 31.255 68.115 ;
        RECT 67.515 67.710 67.885 68.110 ;
        RECT 104.045 68.030 104.415 68.430 ;
        RECT 106.215 68.325 109.560 68.695 ;
        RECT 110.625 68.325 112.240 68.695 ;
        RECT 107.190 68.080 107.560 68.085 ;
        RECT 110.625 68.080 110.995 68.325 ;
        RECT 107.175 67.710 110.995 68.080 ;
        RECT 35.810 66.250 36.280 67.480 ;
        RECT 48.405 66.250 48.875 67.480 ;
        RECT 61.000 66.250 61.470 67.480 ;
        RECT 67.515 67.340 83.370 67.710 ;
        RECT 67.515 66.670 89.065 67.040 ;
        RECT 67.515 66.270 67.885 66.670 ;
        RECT 30.885 65.615 31.255 66.015 ;
        RECT 72.550 65.635 73.320 66.005 ;
        RECT 74.835 65.650 75.605 66.020 ;
        RECT 77.120 65.650 77.890 66.020 ;
        RECT 79.395 65.650 80.165 66.020 ;
        RECT 81.690 65.650 82.460 66.020 ;
        RECT 84.000 65.650 84.770 66.020 ;
        RECT 30.145 65.105 30.515 65.505 ;
        RECT 30.885 65.245 61.605 65.615 ;
        RECT 66.840 65.105 67.210 65.505 ;
        RECT 30.145 64.735 67.215 65.105 ;
        RECT 35.810 62.360 36.280 63.590 ;
        RECT 48.405 62.360 48.875 63.590 ;
        RECT 60.995 62.360 61.465 63.590 ;
        RECT 30.145 61.725 30.515 62.125 ;
        RECT 66.840 61.725 67.210 62.125 ;
        RECT 30.145 61.355 67.215 61.725 ;
        RECT 71.650 61.275 71.930 65.505 ;
        RECT 73.940 61.275 74.220 65.505 ;
        RECT 76.230 61.275 76.510 65.505 ;
        RECT 78.520 61.275 78.800 65.505 ;
        RECT 80.810 61.275 81.090 65.505 ;
        RECT 83.100 61.275 83.380 65.505 ;
        RECT 85.390 61.275 85.670 65.505 ;
        RECT 92.335 65.370 100.965 66.250 ;
        RECT 95.905 63.010 96.185 64.240 ;
        RECT 97.195 63.010 97.475 64.240 ;
        RECT 98.485 63.010 98.765 64.240 ;
        RECT 99.775 63.005 100.055 64.235 ;
        RECT 101.065 63.010 101.345 64.240 ;
        RECT 107.225 63.105 107.505 66.585 ;
        RECT 108.505 63.105 108.785 66.585 ;
        RECT 109.785 63.140 110.065 66.620 ;
        RECT 112.710 66.520 138.145 66.895 ;
        RECT 112.715 64.795 113.085 66.520 ;
        RECT 142.680 62.775 149.515 63.415 ;
        RECT 29.475 60.705 29.845 61.105 ;
        RECT 72.550 60.730 73.320 61.100 ;
        RECT 74.835 60.730 75.605 61.100 ;
        RECT 77.120 60.730 77.890 61.100 ;
        RECT 79.395 60.730 80.165 61.100 ;
        RECT 81.690 60.730 82.460 61.100 ;
        RECT 84.000 60.730 84.770 61.100 ;
        RECT 92.335 60.995 103.740 61.875 ;
        RECT 104.725 61.475 105.100 61.875 ;
        RECT 107.175 61.615 110.140 61.985 ;
        RECT 104.045 60.850 104.420 61.250 ;
        RECT 104.720 61.105 110.990 61.475 ;
        RECT 29.475 60.335 61.620 60.705 ;
        RECT 104.045 60.480 110.310 60.850 ;
        RECT 110.610 60.705 110.990 61.105 ;
        RECT 67.515 60.080 67.885 60.480 ;
        RECT 109.930 60.080 110.310 60.480 ;
        RECT 67.510 59.710 84.770 60.080 ;
        RECT 142.680 59.815 149.110 60.455 ;
        RECT 71.395 59.200 83.625 59.570 ;
        RECT 67.515 58.550 67.885 58.950 ;
        RECT 71.600 58.690 85.720 59.060 ;
        RECT 66.840 58.040 67.210 58.440 ;
        RECT 67.515 58.180 74.570 58.550 ;
        RECT 97.145 58.445 111.670 58.815 ;
        RECT 66.840 57.670 76.375 58.040 ;
        RECT 92.295 57.835 104.205 58.205 ;
        RECT 111.290 58.045 111.670 58.445 ;
        RECT 74.555 57.130 74.935 57.530 ;
        RECT 75.995 57.270 76.375 57.670 ;
        RECT 108.595 57.605 108.965 58.005 ;
        RECT 112.710 57.605 113.080 57.840 ;
        RECT 98.860 57.235 113.090 57.605 ;
        RECT 39.300 56.760 90.215 57.130 ;
        RECT 112.710 57.070 113.080 57.235 ;
        RECT 142.680 57.220 149.110 57.860 ;
        RECT 89.245 56.585 90.120 56.760 ;
        RECT 91.390 56.685 110.990 57.055 ;
        RECT 60.400 56.185 75.695 56.555 ;
        RECT 110.610 56.285 110.990 56.685 ;
        RECT 34.900 55.740 57.525 56.110 ;
        RECT 75.315 55.785 75.685 56.185 ;
        RECT 149.180 56.165 149.550 56.235 ;
        RECT 151.610 56.165 151.980 56.235 ;
        RECT 163.340 56.165 163.710 56.235 ;
        RECT 147.810 56.025 163.710 56.165 ;
        RECT 149.180 55.955 149.550 56.025 ;
        RECT 151.610 55.955 151.980 56.025 ;
        RECT 163.340 55.955 163.710 56.025 ;
        RECT 105.175 55.795 105.495 55.805 ;
        RECT 36.500 53.625 36.780 55.105 ;
        RECT 39.350 53.625 39.630 55.105 ;
        RECT 44.490 53.625 44.770 55.105 ;
        RECT 47.340 53.625 47.620 55.105 ;
        RECT 52.480 53.625 52.760 55.105 ;
        RECT 78.520 53.670 78.800 55.755 ;
        RECT 91.440 53.665 91.720 55.750 ;
        RECT 98.910 53.670 99.190 55.755 ;
        RECT 102.015 53.660 105.505 55.795 ;
        RECT 166.075 55.710 166.445 55.780 ;
        RECT 151.350 55.570 167.280 55.710 ;
        RECT 147.820 55.360 148.190 55.435 ;
        RECT 150.240 55.360 150.610 55.430 ;
        RECT 151.350 55.360 151.490 55.570 ;
        RECT 166.075 55.500 166.445 55.570 ;
        RECT 143.510 55.190 143.880 55.265 ;
        RECT 144.560 55.190 144.930 55.265 ;
        RECT 143.510 55.050 144.930 55.190 ;
        RECT 147.820 55.220 151.490 55.360 ;
        RECT 166.075 55.250 166.445 55.320 ;
        RECT 147.820 55.155 148.190 55.220 ;
        RECT 150.240 55.150 150.610 55.220 ;
        RECT 143.510 54.985 143.880 55.050 ;
        RECT 144.560 54.985 144.930 55.050 ;
        RECT 164.105 55.110 166.445 55.250 ;
        RECT 162.575 54.895 162.905 54.945 ;
        RECT 164.105 54.895 164.245 55.110 ;
        RECT 166.075 55.040 166.445 55.110 ;
        RECT 165.425 54.895 165.755 54.945 ;
        RECT 162.575 54.755 165.755 54.895 ;
        RECT 162.575 54.685 162.905 54.755 ;
        RECT 165.425 54.685 165.755 54.755 ;
        RECT 163.330 54.520 163.700 54.530 ;
        RECT 162.580 54.260 162.900 54.520 ;
        RECT 163.330 54.460 163.850 54.520 ;
        RECT 164.480 54.460 164.800 54.520 ;
        RECT 163.330 54.320 164.800 54.460 ;
        RECT 163.330 54.260 163.850 54.320 ;
        RECT 164.480 54.260 164.800 54.320 ;
        RECT 165.430 54.260 165.750 54.520 ;
        RECT 163.330 54.250 163.700 54.260 ;
        RECT 102.030 53.630 102.350 53.660 ;
        RECT 105.175 53.640 105.495 53.660 ;
        RECT 144.560 53.440 144.930 53.720 ;
        RECT 148.715 53.210 148.995 53.580 ;
        RECT 162.365 53.470 162.685 53.530 ;
        RECT 165.215 53.470 165.535 53.530 ;
        RECT 168.165 53.470 168.535 53.540 ;
        RECT 162.365 53.330 168.535 53.470 ;
        RECT 162.365 53.270 162.685 53.330 ;
        RECT 165.215 53.270 165.535 53.330 ;
        RECT 168.165 53.260 168.535 53.330 ;
        RECT 52.230 52.990 53.015 52.995 ;
        RECT 34.900 52.620 57.840 52.990 ;
        RECT 75.315 52.665 75.685 53.065 ;
        RECT 60.400 52.295 75.695 52.665 ;
        RECT 39.300 51.600 74.935 51.970 ;
        RECT 143.585 51.785 143.955 51.855 ;
        RECT 149.455 51.785 149.825 51.855 ;
        RECT 163.345 51.810 163.605 51.900 ;
        RECT 164.295 51.810 164.555 51.900 ;
        RECT 169.105 51.810 169.475 51.880 ;
        RECT 161.345 51.785 161.715 51.805 ;
        RECT 143.585 51.645 161.715 51.785 ;
        RECT 45.605 51.410 49.765 51.415 ;
        RECT 44.440 51.040 49.765 51.410 ;
        RECT 74.555 51.200 74.925 51.600 ;
        RECT 143.585 51.575 143.955 51.645 ;
        RECT 149.455 51.575 149.825 51.645 ;
        RECT 161.345 51.525 161.715 51.645 ;
        RECT 163.345 51.670 169.475 51.810 ;
        RECT 163.345 51.570 163.605 51.670 ;
        RECT 164.295 51.570 164.555 51.670 ;
        RECT 169.105 51.600 169.475 51.670 ;
        RECT 148.685 51.435 149.055 51.505 ;
        RECT 152.640 51.435 153.010 51.505 ;
        RECT 148.685 51.295 153.010 51.435 ;
        RECT 162.630 51.310 163.000 51.380 ;
        RECT 148.685 51.225 149.055 51.295 ;
        RECT 152.640 51.225 153.010 51.295 ;
        RECT 159.780 51.170 163.000 51.310 ;
        RECT 145.455 51.085 145.825 51.155 ;
        RECT 151.015 51.085 151.385 51.155 ;
        RECT 159.780 51.085 159.925 51.170 ;
        RECT 162.630 51.100 163.000 51.170 ;
        RECT 163.340 51.370 163.710 51.380 ;
        RECT 163.340 51.310 163.850 51.370 ;
        RECT 164.480 51.310 164.800 51.370 ;
        RECT 163.340 51.170 164.800 51.310 ;
        RECT 163.340 51.110 163.850 51.170 ;
        RECT 164.480 51.110 164.800 51.170 ;
        RECT 163.340 51.100 163.710 51.110 ;
        RECT 145.455 50.945 159.925 51.085 ;
        RECT 145.455 50.875 145.825 50.945 ;
        RECT 151.015 50.875 151.385 50.945 ;
        RECT 162.575 50.875 162.905 50.925 ;
        RECT 165.425 50.875 165.755 50.925 ;
        RECT 162.575 50.735 165.755 50.875 ;
        RECT 162.575 50.665 162.905 50.735 ;
        RECT 161.345 50.495 161.715 50.565 ;
        RECT 164.105 50.495 164.245 50.735 ;
        RECT 165.425 50.665 165.755 50.735 ;
        RECT 166.060 50.495 166.430 50.565 ;
        RECT 161.345 50.355 166.430 50.495 ;
        RECT 161.345 50.285 161.715 50.355 ;
        RECT 166.060 50.285 166.430 50.355 ;
        RECT 143.615 49.985 143.985 49.995 ;
        RECT 143.610 49.725 143.985 49.985 ;
        RECT 145.930 49.725 146.300 50.005 ;
        RECT 149.460 49.895 149.830 49.965 ;
        RECT 149.460 49.755 151.300 49.895 ;
        RECT 143.615 49.715 143.985 49.725 ;
        RECT 149.460 49.685 149.830 49.755 ;
        RECT 150.110 49.485 150.460 49.545 ;
        RECT 151.160 49.485 151.300 49.755 ;
        RECT 161.685 49.755 162.585 49.825 ;
        RECT 168.165 49.755 168.535 49.805 ;
        RECT 161.685 49.615 168.580 49.755 ;
        RECT 161.685 49.545 162.585 49.615 ;
        RECT 152.000 49.485 152.350 49.545 ;
        RECT 168.165 49.525 168.535 49.615 ;
        RECT 150.110 49.345 152.350 49.485 ;
        RECT 150.110 49.285 150.460 49.345 ;
        RECT 152.000 49.285 152.350 49.345 ;
        RECT 165.980 49.385 166.880 49.455 ;
        RECT 169.105 49.385 169.475 49.455 ;
        RECT 165.980 49.245 169.475 49.385 ;
        RECT 165.980 49.175 166.880 49.245 ;
        RECT 169.105 49.175 169.475 49.245 ;
        RECT 151.055 49.095 151.425 49.105 ;
        RECT 150.760 48.835 151.705 49.095 ;
        RECT 151.055 48.825 151.425 48.835 ;
        RECT 143.585 48.785 143.955 48.795 ;
        RECT 143.585 48.525 143.960 48.785 ;
        RECT 143.585 48.515 143.955 48.525 ;
        RECT 145.915 48.520 146.285 48.800 ;
        RECT 150.440 48.580 150.760 48.660 ;
        RECT 151.640 48.580 152.020 48.640 ;
        RECT 152.640 48.580 153.010 48.650 ;
        RECT 150.440 48.440 153.010 48.580 ;
        RECT 150.440 48.400 150.760 48.440 ;
        RECT 151.640 48.395 152.020 48.440 ;
        RECT 151.700 48.380 152.020 48.395 ;
        RECT 152.640 48.370 153.010 48.440 ;
        RECT 149.460 48.205 149.830 48.345 ;
        RECT 151.070 48.205 151.390 48.255 ;
        RECT 149.460 48.065 152.110 48.205 ;
        RECT 151.070 47.995 151.390 48.065 ;
        RECT 149.810 47.840 150.130 47.880 ;
        RECT 152.330 47.840 152.650 47.880 ;
        RECT 149.810 47.700 152.650 47.840 ;
        RECT 149.810 47.620 150.130 47.700 ;
        RECT 49.395 47.100 49.765 47.500 ;
        RECT 32.605 46.730 49.765 47.100 ;
        RECT 52.285 47.105 52.655 47.505 ;
        RECT 73.800 47.105 74.170 47.505 ;
        RECT 151.130 47.455 151.270 47.700 ;
        RECT 152.330 47.620 152.650 47.700 ;
        RECT 151.015 47.445 151.385 47.455 ;
        RECT 150.760 47.380 151.705 47.445 ;
        RECT 150.085 47.240 152.545 47.380 ;
        RECT 150.760 47.185 151.705 47.240 ;
        RECT 151.015 47.175 151.385 47.185 ;
        RECT 52.285 46.735 74.180 47.105 ;
        RECT 150.110 46.935 150.460 46.995 ;
        RECT 152.000 46.935 152.350 47.040 ;
        RECT 143.680 46.615 144.050 46.895 ;
        RECT 145.775 46.615 146.145 46.895 ;
        RECT 150.110 46.795 152.350 46.935 ;
        RECT 150.110 46.735 150.460 46.795 ;
        RECT 149.460 46.595 149.830 46.665 ;
        RECT 151.160 46.595 151.300 46.795 ;
        RECT 152.000 46.780 152.350 46.795 ;
        RECT 30.615 46.080 30.985 46.480 ;
        RECT 149.460 46.455 151.300 46.595 ;
        RECT 149.460 46.385 149.830 46.455 ;
        RECT 30.615 45.710 49.025 46.080 ;
        RECT 48.655 45.680 49.025 45.710 ;
        RECT 51.545 45.715 73.420 46.085 ;
        RECT 48.655 45.310 51.175 45.680 ;
        RECT 51.545 45.315 51.915 45.715 ;
        RECT 73.040 45.315 73.410 45.715 ;
        RECT 151.015 45.435 151.385 45.505 ;
        RECT 154.430 45.435 154.800 45.505 ;
        RECT 34.695 42.700 35.065 45.075 ;
        RECT 39.275 42.700 39.645 45.075 ;
        RECT 43.860 42.700 44.230 45.075 ;
        RECT 50.805 44.910 51.175 45.310 ;
        RECT 151.015 45.295 154.800 45.435 ;
        RECT 151.015 45.225 151.385 45.295 ;
        RECT 154.430 45.225 154.800 45.295 ;
        RECT 58.075 42.580 58.445 45.180 ;
        RECT 62.650 42.580 63.020 45.180 ;
        RECT 67.235 42.580 67.605 45.180 ;
        RECT 88.300 42.925 88.580 45.010 ;
        RECT 149.460 44.555 149.830 44.625 ;
        RECT 150.515 44.555 150.885 44.625 ;
        RECT 149.460 44.415 150.885 44.555 ;
        RECT 149.460 44.345 149.830 44.415 ;
        RECT 150.515 44.345 150.885 44.415 ;
        RECT 159.530 43.520 169.045 43.855 ;
        RECT 159.520 42.750 169.045 43.085 ;
        RECT 30.615 41.540 30.985 41.940 ;
        RECT 32.325 41.680 49.765 42.050 ;
        RECT 30.615 41.170 49.025 41.540 ;
        RECT 49.395 41.280 49.765 41.680 ;
        RECT 50.805 41.680 72.660 42.050 ;
        RECT 48.655 41.140 49.025 41.170 ;
        RECT 50.805 41.140 51.175 41.680 ;
        RECT 73.040 41.540 73.410 41.940 ;
        RECT 74.560 41.790 74.930 42.190 ;
        RECT 150.515 42.040 150.885 42.045 ;
        RECT 150.515 42.035 151.060 42.040 ;
        RECT 32.325 40.660 48.285 41.030 ;
        RECT 48.655 40.770 51.175 41.140 ;
        RECT 51.545 41.170 73.420 41.540 ;
        RECT 74.555 41.420 90.120 41.790 ;
        RECT 150.515 41.775 151.380 42.035 ;
        RECT 153.620 41.975 153.940 42.035 ;
        RECT 154.430 41.975 154.800 42.045 ;
        RECT 153.620 41.835 154.800 41.975 ;
        RECT 153.620 41.775 153.940 41.835 ;
        RECT 150.515 41.765 151.060 41.775 ;
        RECT 154.430 41.765 154.800 41.835 ;
        RECT 51.545 40.770 51.915 41.170 ;
        RECT 47.915 40.260 48.285 40.660 ;
        RECT 52.285 40.660 72.660 41.030 ;
        RECT 52.285 40.260 52.655 40.660 ;
        RECT 73.800 40.280 74.170 40.680 ;
        RECT 74.555 40.600 74.935 41.420 ;
        RECT 75.995 40.790 76.365 41.190 ;
        RECT 143.680 40.980 144.050 41.260 ;
        RECT 145.775 40.980 146.145 41.260 ;
        RECT 75.995 40.420 81.635 40.790 ;
        RECT 34.695 37.640 35.065 40.015 ;
        RECT 39.275 37.645 39.645 40.020 ;
        RECT 43.860 37.645 44.230 40.020 ;
        RECT 58.075 37.530 58.445 40.130 ;
        RECT 62.645 37.690 63.030 40.130 ;
        RECT 67.220 37.690 67.605 40.130 ;
        RECT 73.800 39.910 79.160 40.280 ;
        RECT 75.315 38.890 80.830 39.260 ;
        RECT 159.525 39.250 169.015 39.585 ;
        RECT 75.325 38.490 75.695 38.890 ;
        RECT 159.525 38.480 169.015 38.815 ;
        RECT 78.440 37.820 78.720 38.300 ;
        RECT 81.020 37.820 81.300 38.300 ;
        RECT 62.660 37.530 63.030 37.690 ;
        RECT 67.235 37.530 67.605 37.690 ;
        RECT 47.915 37.000 48.285 37.400 ;
        RECT 30.615 36.490 30.985 36.890 ;
        RECT 32.720 36.630 48.285 37.000 ;
        RECT 52.285 37.000 52.655 37.400 ;
        RECT 73.805 37.000 74.180 37.400 ;
        RECT 48.655 36.520 51.175 36.890 ;
        RECT 48.655 36.490 49.025 36.520 ;
        RECT 30.615 36.120 49.025 36.490 ;
        RECT 49.395 35.980 49.765 36.380 ;
        RECT 32.720 35.610 49.765 35.980 ;
        RECT 50.805 35.980 51.175 36.520 ;
        RECT 51.545 36.490 51.915 36.890 ;
        RECT 52.285 36.630 74.180 37.000 ;
        RECT 75.315 37.235 75.685 37.635 ;
        RECT 75.315 37.230 76.260 37.235 ;
        RECT 75.315 36.865 80.830 37.230 ;
        RECT 76.075 36.860 80.830 36.865 ;
        RECT 51.545 36.120 73.420 36.490 ;
        RECT 50.805 35.610 70.135 35.980 ;
        RECT 73.040 35.720 73.410 36.120 ;
        RECT 75.315 36.050 75.685 36.450 ;
        RECT 75.315 35.680 82.175 36.050 ;
        RECT 34.695 32.575 35.065 34.950 ;
        RECT 39.275 32.575 39.645 34.950 ;
        RECT 43.860 32.575 44.230 34.950 ;
        RECT 50.805 32.350 51.175 32.750 ;
        RECT 58.070 32.580 58.455 35.020 ;
        RECT 62.650 32.580 63.035 35.020 ;
        RECT 67.225 32.580 67.610 35.020 ;
        RECT 74.555 34.940 90.120 35.310 ;
        RECT 74.555 34.540 74.925 34.940 ;
        RECT 79.075 32.610 79.355 33.840 ;
        RECT 81.655 32.610 81.935 33.840 ;
        RECT 30.615 31.950 30.985 32.350 ;
        RECT 48.655 31.980 51.175 32.350 ;
        RECT 48.655 31.950 49.025 31.980 ;
        RECT 30.615 31.580 49.025 31.950 ;
        RECT 51.545 31.950 51.915 32.350 ;
        RECT 73.040 31.980 73.415 32.350 ;
        RECT 73.040 31.950 73.410 31.980 ;
        RECT 51.545 31.580 73.410 31.950 ;
        RECT 74.560 31.510 74.930 31.910 ;
        RECT 33.370 30.560 49.765 30.930 ;
        RECT 49.395 30.160 49.765 30.560 ;
        RECT 50.805 30.560 72.660 30.930 ;
        RECT 74.555 30.630 90.120 31.510 ;
        RECT 50.805 30.160 51.175 30.560 ;
        RECT 74.560 30.230 74.930 30.630 ;
        RECT 79.345 28.550 79.625 29.530 ;
        RECT 112.715 28.190 113.085 29.425 ;
        RECT 74.555 27.450 74.925 27.850 ;
        RECT 112.710 27.815 138.495 28.190 ;
        RECT 74.555 27.080 90.120 27.450 ;
        RECT 29.935 26.270 30.305 26.670 ;
        RECT 61.555 26.410 88.945 26.780 ;
        RECT 29.250 25.760 29.620 26.160 ;
        RECT 29.935 25.900 88.735 26.270 ;
        RECT 103.840 25.960 113.775 26.330 ;
        RECT 29.250 25.390 89.495 25.760 ;
        RECT 94.675 25.450 122.935 25.820 ;
        RECT 89.115 24.990 89.485 25.390 ;
        RECT 38.650 24.370 41.420 24.740 ;
        RECT 57.765 24.370 60.535 24.740 ;
        RECT 64.200 24.370 66.970 24.740 ;
        RECT 70.470 24.370 73.240 24.740 ;
        RECT 76.515 24.370 79.285 24.740 ;
        RECT 90.970 24.465 124.065 25.310 ;
        RECT 57.810 24.360 60.490 24.370 ;
        RECT 64.245 24.360 66.925 24.370 ;
        RECT 70.515 24.360 73.195 24.370 ;
        RECT 76.560 24.360 79.240 24.370 ;
        RECT 36.770 14.310 37.050 24.290 ;
        RECT 55.900 14.305 56.180 24.290 ;
        RECT 62.190 14.310 62.470 24.290 ;
        RECT 68.480 14.310 68.760 24.290 ;
        RECT 74.770 14.310 75.050 24.290 ;
        RECT 81.060 14.310 81.340 24.290 ;
        RECT 93.575 23.805 94.255 23.810 ;
        RECT 93.530 23.435 94.300 23.805 ;
        RECT 95.865 23.790 96.545 23.795 ;
        RECT 98.155 23.790 98.835 23.795 ;
        RECT 100.445 23.790 101.125 23.795 ;
        RECT 102.735 23.790 103.415 23.795 ;
        RECT 105.025 23.790 105.705 23.795 ;
        RECT 107.315 23.790 107.995 23.795 ;
        RECT 109.605 23.790 110.285 23.795 ;
        RECT 111.895 23.790 112.575 23.795 ;
        RECT 114.185 23.790 114.865 23.795 ;
        RECT 116.475 23.790 117.155 23.795 ;
        RECT 118.765 23.790 119.445 23.795 ;
        RECT 121.055 23.790 121.735 23.795 ;
        RECT 123.345 23.790 124.025 23.795 ;
        RECT 93.575 23.430 94.255 23.435 ;
        RECT 95.820 23.420 96.590 23.790 ;
        RECT 98.110 23.420 98.880 23.790 ;
        RECT 100.400 23.420 101.170 23.790 ;
        RECT 102.690 23.420 103.460 23.790 ;
        RECT 104.980 23.420 105.750 23.790 ;
        RECT 107.270 23.420 108.040 23.790 ;
        RECT 109.560 23.420 110.330 23.790 ;
        RECT 111.850 23.420 112.620 23.790 ;
        RECT 114.140 23.420 114.910 23.790 ;
        RECT 116.430 23.420 117.200 23.790 ;
        RECT 118.720 23.420 119.490 23.790 ;
        RECT 121.010 23.420 121.780 23.790 ;
        RECT 123.300 23.420 124.070 23.790 ;
        RECT 95.865 23.415 96.545 23.420 ;
        RECT 98.155 23.415 98.835 23.420 ;
        RECT 100.445 23.415 101.125 23.420 ;
        RECT 102.735 23.415 103.415 23.420 ;
        RECT 105.025 23.415 105.705 23.420 ;
        RECT 107.315 23.415 107.995 23.420 ;
        RECT 109.605 23.415 110.285 23.420 ;
        RECT 111.895 23.415 112.575 23.420 ;
        RECT 114.185 23.415 114.865 23.420 ;
        RECT 116.475 23.415 117.155 23.420 ;
        RECT 118.765 23.415 119.445 23.420 ;
        RECT 121.055 23.415 121.735 23.420 ;
        RECT 123.345 23.415 124.025 23.420 ;
        RECT 94.920 22.110 95.200 23.335 ;
        RECT 99.500 22.110 99.780 23.335 ;
        RECT 104.080 22.110 104.360 23.335 ;
        RECT 108.660 22.110 108.940 23.335 ;
        RECT 113.240 22.110 113.520 23.335 ;
        RECT 117.820 22.110 118.100 23.335 ;
        RECT 122.400 22.110 122.680 23.335 ;
        RECT 93.575 22.030 94.255 22.035 ;
        RECT 95.865 22.030 96.545 22.035 ;
        RECT 98.155 22.030 98.835 22.035 ;
        RECT 100.445 22.030 101.125 22.035 ;
        RECT 102.735 22.030 103.415 22.035 ;
        RECT 105.025 22.030 105.705 22.035 ;
        RECT 107.315 22.030 107.995 22.035 ;
        RECT 109.605 22.030 110.285 22.035 ;
        RECT 111.895 22.030 112.575 22.035 ;
        RECT 114.180 22.030 114.860 22.035 ;
        RECT 116.475 22.030 117.155 22.035 ;
        RECT 118.765 22.030 119.445 22.035 ;
        RECT 121.055 22.030 121.735 22.035 ;
        RECT 123.345 22.030 124.025 22.035 ;
        RECT 93.530 21.660 94.300 22.030 ;
        RECT 95.820 21.660 96.590 22.030 ;
        RECT 98.110 21.660 98.880 22.030 ;
        RECT 100.400 21.660 101.170 22.030 ;
        RECT 102.690 21.660 103.460 22.030 ;
        RECT 104.980 21.660 105.750 22.030 ;
        RECT 107.270 21.660 108.040 22.030 ;
        RECT 109.560 21.660 110.330 22.030 ;
        RECT 111.850 21.660 112.620 22.030 ;
        RECT 114.135 21.660 114.905 22.030 ;
        RECT 116.430 21.660 117.200 22.030 ;
        RECT 118.720 21.660 119.490 22.030 ;
        RECT 121.010 21.660 121.780 22.030 ;
        RECT 123.300 21.660 124.070 22.030 ;
        RECT 93.575 21.655 94.255 21.660 ;
        RECT 95.865 21.655 96.545 21.660 ;
        RECT 98.155 21.655 98.835 21.660 ;
        RECT 100.445 21.655 101.125 21.660 ;
        RECT 102.735 21.655 103.415 21.660 ;
        RECT 105.025 21.655 105.705 21.660 ;
        RECT 107.315 21.655 107.995 21.660 ;
        RECT 109.605 21.655 110.285 21.660 ;
        RECT 111.895 21.655 112.575 21.660 ;
        RECT 114.180 21.655 114.860 21.660 ;
        RECT 116.475 21.655 117.155 21.660 ;
        RECT 118.765 21.655 119.445 21.660 ;
        RECT 121.055 21.655 121.735 21.660 ;
        RECT 123.345 21.655 124.025 21.660 ;
        RECT 90.970 20.145 124.065 20.990 ;
        RECT 38.650 13.820 41.420 14.190 ;
        RECT 57.765 13.820 60.535 14.190 ;
        RECT 64.200 13.820 66.970 14.190 ;
        RECT 70.470 13.820 73.240 14.190 ;
        RECT 76.515 13.820 79.285 14.190 ;
        RECT 29.255 13.170 29.625 13.570 ;
        RECT 89.115 13.170 89.485 13.570 ;
        RECT 29.255 12.800 89.495 13.170 ;
      LAYER met3 ;
        RECT 29.475 58.575 29.845 73.395 ;
        RECT 48.260 73.025 49.030 73.395 ;
        RECT 29.255 58.205 29.845 58.575 ;
        RECT 29.255 26.160 29.635 58.205 ;
        RECT 30.145 57.905 30.515 72.375 ;
        RECT 35.655 72.005 36.425 72.375 ;
        RECT 35.760 70.140 36.330 72.005 ;
        RECT 48.355 70.140 48.925 73.025 ;
        RECT 60.840 72.005 61.610 72.375 ;
        RECT 60.945 71.345 61.515 72.005 ;
        RECT 60.940 70.165 61.515 71.345 ;
        RECT 60.945 70.140 61.515 70.165 ;
        RECT 29.250 25.390 29.635 26.160 ;
        RECT 29.935 57.535 30.515 57.905 ;
        RECT 29.935 25.900 30.315 57.535 ;
        RECT 30.885 57.250 31.255 68.485 ;
        RECT 35.650 68.115 36.420 68.485 ;
        RECT 48.255 68.115 49.025 68.485 ;
        RECT 60.815 68.115 61.585 68.485 ;
        RECT 35.760 65.615 36.330 68.115 ;
        RECT 48.355 65.615 48.925 68.115 ;
        RECT 60.945 67.455 61.515 68.115 ;
        RECT 60.945 66.275 61.520 67.455 ;
        RECT 60.945 65.615 61.515 66.275 ;
        RECT 35.655 65.245 36.425 65.615 ;
        RECT 48.230 65.245 49.000 65.615 ;
        RECT 60.835 65.245 61.605 65.615 ;
        RECT 35.760 60.705 36.330 63.590 ;
        RECT 48.355 61.725 48.925 63.590 ;
        RECT 48.265 61.355 49.035 61.725 ;
        RECT 60.945 60.705 61.515 63.590 ;
        RECT 35.660 60.335 36.430 60.705 ;
        RECT 60.850 60.335 61.620 60.705 ;
        RECT 66.840 57.850 67.215 72.775 ;
        RECT 67.515 58.180 67.885 74.670 ;
        RECT 72.010 73.265 72.780 74.670 ;
        RECT 73.130 74.300 73.900 74.670 ;
        RECT 72.010 67.340 72.780 68.730 ;
        RECT 73.335 67.710 73.715 74.300 ;
        RECT 74.295 73.265 75.065 74.670 ;
        RECT 76.540 73.265 77.310 74.670 ;
        RECT 77.705 74.300 78.475 74.670 ;
        RECT 73.145 67.340 73.915 67.710 ;
        RECT 74.295 67.340 75.065 68.730 ;
        RECT 76.540 67.340 77.310 68.730 ;
        RECT 77.915 67.710 78.295 74.300 ;
        RECT 78.860 73.265 79.630 74.670 ;
        RECT 113.600 73.375 114.370 73.745 ;
        RECT 114.880 73.375 115.650 73.745 ;
        RECT 93.965 68.800 94.345 73.015 ;
        RECT 96.545 69.400 96.925 73.040 ;
        RECT 99.125 69.400 99.505 73.040 ;
        RECT 96.545 69.030 97.315 69.400 ;
        RECT 98.515 69.030 99.505 69.400 ;
        RECT 77.725 67.340 78.495 67.710 ;
        RECT 78.860 67.340 79.630 68.730 ;
        RECT 93.945 68.430 94.720 68.800 ;
        RECT 95.460 68.430 96.235 68.800 ;
        RECT 72.550 65.635 73.320 67.040 ;
        RECT 74.835 65.635 75.605 67.040 ;
        RECT 77.120 65.635 77.890 67.040 ;
        RECT 79.395 65.635 80.165 67.040 ;
        RECT 81.690 65.635 82.460 67.040 ;
        RECT 84.000 65.635 84.770 67.040 ;
        RECT 71.600 59.060 71.980 65.505 ;
        RECT 72.550 59.710 73.320 61.100 ;
        RECT 73.890 59.570 74.270 65.505 ;
        RECT 74.835 59.710 75.605 61.100 ;
        RECT 73.690 59.200 74.460 59.570 ;
        RECT 76.180 59.060 76.560 65.505 ;
        RECT 77.120 59.690 77.890 61.100 ;
        RECT 78.470 59.570 78.850 65.505 ;
        RECT 79.395 59.710 80.165 61.100 ;
        RECT 78.280 59.200 79.050 59.570 ;
        RECT 71.600 58.690 73.420 59.060 ;
        RECT 75.990 58.690 76.760 59.060 ;
        RECT 66.840 57.670 67.210 57.850 ;
        RECT 30.615 56.880 31.255 57.250 ;
        RECT 30.615 31.580 30.995 56.880 ;
        RECT 39.300 56.760 40.070 57.130 ;
        RECT 47.290 56.760 48.060 57.130 ;
        RECT 36.245 55.740 37.015 56.110 ;
        RECT 36.450 52.990 36.830 55.740 ;
        RECT 36.240 52.620 37.025 52.990 ;
        RECT 39.300 51.970 39.680 56.760 ;
        RECT 44.230 55.740 45.015 56.110 ;
        RECT 44.440 52.990 44.820 55.740 ;
        RECT 44.235 52.620 45.020 52.990 ;
        RECT 39.300 51.600 40.085 51.970 ;
        RECT 44.440 51.410 44.820 52.620 ;
        RECT 47.290 51.970 47.670 56.760 ;
        RECT 52.215 55.740 53.000 56.110 ;
        RECT 52.430 52.995 52.810 55.740 ;
        RECT 52.230 52.625 53.015 52.995 ;
        RECT 52.430 52.620 52.810 52.625 ;
        RECT 47.290 51.600 48.285 51.970 ;
        RECT 44.440 51.040 45.225 51.410 ;
        RECT 39.065 46.730 39.835 47.100 ;
        RECT 34.485 45.710 35.255 46.080 ;
        RECT 34.695 45.050 35.065 45.710 ;
        RECT 39.275 45.050 39.645 46.730 ;
        RECT 43.660 45.710 44.430 46.080 ;
        RECT 43.860 45.050 44.230 45.710 ;
        RECT 34.645 42.725 35.115 45.050 ;
        RECT 39.225 42.725 39.695 45.050 ;
        RECT 43.810 42.725 44.280 45.050 ;
        RECT 34.490 41.680 35.260 42.050 ;
        RECT 43.655 41.680 44.425 42.050 ;
        RECT 34.695 39.990 35.065 41.680 ;
        RECT 39.060 40.660 39.830 41.030 ;
        RECT 39.275 39.995 39.645 40.660 ;
        RECT 43.860 39.995 44.230 41.680 ;
        RECT 34.645 37.665 35.115 39.990 ;
        RECT 39.225 37.670 39.695 39.995 ;
        RECT 43.810 37.670 44.280 39.995 ;
        RECT 34.695 35.980 35.065 37.665 ;
        RECT 39.275 37.000 39.645 37.670 ;
        RECT 39.070 36.630 39.840 37.000 ;
        RECT 43.860 35.980 44.230 37.670 ;
        RECT 47.915 36.630 48.285 51.600 ;
        RECT 49.395 51.410 49.765 51.415 ;
        RECT 48.980 51.040 49.765 51.410 ;
        RECT 34.485 35.610 35.255 35.980 ;
        RECT 43.650 35.610 44.420 35.980 ;
        RECT 34.645 32.600 35.115 34.925 ;
        RECT 39.225 32.600 39.695 34.925 ;
        RECT 43.810 32.600 44.280 34.925 ;
        RECT 34.695 31.950 35.065 32.600 ;
        RECT 34.495 31.580 35.265 31.950 ;
        RECT 34.695 31.575 35.065 31.580 ;
        RECT 39.275 30.930 39.645 32.600 ;
        RECT 43.860 31.950 44.230 32.600 ;
        RECT 43.650 31.580 44.420 31.950 ;
        RECT 48.655 31.580 49.025 46.080 ;
        RECT 39.075 30.560 39.845 30.930 ;
        RECT 49.395 30.160 49.765 51.040 ;
        RECT 50.805 30.025 51.175 45.680 ;
        RECT 51.545 31.580 51.915 46.085 ;
        RECT 52.285 36.630 52.655 47.505 ;
        RECT 57.875 46.735 58.645 47.105 ;
        RECT 67.030 46.735 67.800 47.105 ;
        RECT 58.025 42.605 58.495 46.735 ;
        RECT 62.425 45.715 63.195 46.085 ;
        RECT 62.600 42.605 63.070 45.715 ;
        RECT 67.185 42.605 67.655 46.735 ;
        RECT 57.870 41.680 58.640 42.050 ;
        RECT 67.040 41.680 67.810 42.050 ;
        RECT 58.015 35.980 58.495 41.680 ;
        RECT 62.465 40.660 63.235 41.030 ;
        RECT 62.610 37.000 63.080 40.660 ;
        RECT 62.460 36.630 63.230 37.000 ;
        RECT 67.175 35.980 67.655 41.680 ;
        RECT 57.855 35.610 58.625 35.980 ;
        RECT 67.015 35.610 67.785 35.980 ;
        RECT 58.020 31.950 58.505 34.995 ;
        RECT 57.875 31.580 58.645 31.950 ;
        RECT 62.600 30.930 63.085 34.995 ;
        RECT 67.175 31.950 67.660 34.995 ;
        RECT 67.020 31.580 67.790 31.950 ;
        RECT 73.040 31.580 73.420 58.690 ;
        RECT 73.800 58.180 74.570 58.550 ;
        RECT 73.800 36.630 74.180 58.180 ;
        RECT 62.450 30.560 63.220 30.930 ;
        RECT 74.555 27.080 74.935 57.530 ;
        RECT 75.315 35.680 75.695 56.555 ;
        RECT 75.995 40.420 76.375 58.040 ;
        RECT 78.470 53.695 78.850 59.200 ;
        RECT 80.760 59.060 81.140 65.505 ;
        RECT 81.690 59.710 82.460 61.100 ;
        RECT 83.050 59.570 83.430 65.505 ;
        RECT 84.000 59.710 84.770 61.100 ;
        RECT 82.855 59.200 83.625 59.570 ;
        RECT 85.340 59.060 85.720 65.505 ;
        RECT 80.570 58.690 81.340 59.060 ;
        RECT 84.950 58.690 85.720 59.060 ;
        RECT 92.335 57.835 93.210 66.280 ;
        RECT 95.855 63.010 96.235 68.430 ;
        RECT 98.435 68.000 98.895 69.030 ;
        RECT 101.705 68.800 102.085 73.015 ;
        RECT 100.620 68.430 101.395 68.800 ;
        RECT 101.705 68.430 102.475 68.800 ;
        RECT 97.145 58.815 97.525 64.240 ;
        RECT 98.435 63.010 98.815 68.000 ;
        RECT 99.725 58.815 100.105 64.235 ;
        RECT 101.015 63.010 101.395 68.430 ;
        RECT 104.040 60.480 104.420 73.190 ;
        RECT 104.720 61.105 105.100 69.205 ;
        RECT 106.415 68.695 106.795 71.700 ;
        RECT 107.695 69.205 108.075 71.700 ;
        RECT 107.305 68.835 108.075 69.205 ;
        RECT 108.975 68.695 109.355 71.700 ;
        RECT 111.350 69.260 111.730 73.235 ;
        RECT 111.355 68.870 111.725 69.260 ;
        RECT 113.775 69.160 114.155 73.375 ;
        RECT 115.055 69.160 115.435 73.375 ;
        RECT 113.580 68.790 114.350 69.160 ;
        RECT 114.860 68.790 115.630 69.160 ;
        RECT 106.215 68.325 106.985 68.695 ;
        RECT 108.455 68.325 109.560 68.695 ;
        RECT 107.190 68.080 107.560 68.085 ;
        RECT 107.175 67.710 107.975 68.080 ;
        RECT 107.175 61.985 107.555 67.710 ;
        RECT 108.455 63.130 108.835 68.325 ;
        RECT 109.735 67.710 110.530 68.080 ;
        RECT 107.175 61.980 107.605 61.985 ;
        RECT 108.430 61.980 108.970 61.985 ;
        RECT 107.175 61.615 107.970 61.980 ;
        RECT 108.430 61.615 109.215 61.980 ;
        RECT 97.145 58.445 97.925 58.815 ;
        RECT 99.325 58.445 100.105 58.815 ;
        RECT 98.860 57.235 99.645 57.605 ;
        RECT 80.745 40.420 81.635 40.790 ;
        RECT 78.390 39.910 79.160 40.280 ;
        RECT 78.390 37.845 78.770 39.910 ;
        RECT 80.970 37.820 81.350 40.420 ;
        RECT 78.840 35.680 79.610 36.050 ;
        RECT 81.405 35.680 82.175 36.050 ;
        RECT 79.025 32.610 79.405 35.680 ;
        RECT 81.605 32.610 81.985 35.680 ;
        RECT 79.295 30.630 80.065 31.000 ;
        RECT 79.295 27.450 79.675 30.630 ;
        RECT 79.295 27.080 80.065 27.450 ;
        RECT 61.555 26.410 63.125 26.780 ;
        RECT 74.125 26.410 75.695 26.780 ;
        RECT 88.250 26.410 88.945 44.985 ;
        RECT 89.245 27.285 90.120 56.970 ;
        RECT 91.390 56.685 92.175 57.055 ;
        RECT 91.390 53.690 91.770 56.685 ;
        RECT 98.860 53.695 99.240 57.235 ;
        RECT 103.330 53.660 104.205 58.205 ;
        RECT 108.590 57.240 108.970 61.615 ;
        RECT 109.735 61.610 110.115 67.710 ;
        RECT 108.590 57.235 108.965 57.240 ;
        RECT 109.930 46.390 110.310 60.850 ;
        RECT 108.175 46.385 110.310 46.390 ;
        RECT 91.330 44.505 110.310 46.385 ;
        RECT 91.330 41.550 109.190 44.505 ;
        RECT 109.930 41.550 110.310 44.505 ;
        RECT 91.330 39.665 110.310 41.550 ;
        RECT 91.330 36.210 109.190 39.665 ;
        RECT 109.930 36.210 110.310 39.665 ;
        RECT 91.330 34.325 110.310 36.210 ;
        RECT 91.330 33.215 109.190 34.325 ;
        RECT 109.930 33.215 110.310 34.325 ;
        RECT 91.330 31.335 110.310 33.215 ;
        RECT 91.330 31.330 109.555 31.335 ;
        RECT 91.330 29.985 109.190 31.330 ;
        RECT 110.610 27.565 110.990 61.475 ;
        RECT 89.245 26.410 91.845 27.285 ;
        RECT 55.850 25.900 57.420 26.270 ;
        RECT 29.255 12.800 29.635 25.390 ;
        RECT 36.720 25.390 37.890 25.760 ;
        RECT 36.720 13.170 37.100 25.390 ;
        RECT 38.650 24.370 41.420 25.760 ;
        RECT 55.850 14.305 56.230 25.900 ;
        RECT 57.765 24.370 60.535 25.760 ;
        RECT 62.140 14.310 62.520 26.410 ;
        RECT 68.430 26.270 68.810 26.290 ;
        RECT 67.840 25.900 69.410 26.270 ;
        RECT 64.200 24.370 66.970 25.760 ;
        RECT 68.430 14.310 68.810 25.900 ;
        RECT 70.470 24.370 73.240 25.760 ;
        RECT 74.720 14.310 75.100 26.410 ;
        RECT 79.820 25.900 81.390 26.270 ;
        RECT 76.515 24.370 79.285 25.760 ;
        RECT 81.010 14.310 81.390 25.900 ;
        RECT 36.720 12.800 37.890 13.170 ;
        RECT 38.650 12.800 41.420 14.300 ;
        RECT 57.765 12.800 60.535 14.190 ;
        RECT 64.200 12.800 66.970 14.190 ;
        RECT 70.470 12.800 73.240 14.190 ;
        RECT 76.515 12.800 79.285 14.190 ;
        RECT 89.115 12.800 89.495 25.760 ;
        RECT 90.970 20.145 91.845 26.410 ;
        RECT 109.885 27.185 110.990 27.565 ;
        RECT 109.885 26.330 110.380 27.185 ;
        RECT 111.290 26.885 111.670 58.815 ;
        RECT 112.710 27.815 113.090 66.895 ;
        RECT 143.505 57.860 143.805 65.055 ;
        RECT 147.815 60.455 148.115 65.050 ;
        RECT 149.215 63.415 149.515 65.055 ;
        RECT 149.200 62.775 149.530 63.415 ;
        RECT 147.800 59.815 148.130 60.455 ;
        RECT 143.490 57.220 143.820 57.860 ;
        RECT 143.505 55.290 143.805 57.220 ;
        RECT 147.815 55.460 148.115 59.815 ;
        RECT 149.215 56.260 149.515 62.775 ;
        RECT 149.200 55.930 149.530 56.260 ;
        RECT 151.630 55.930 151.960 56.260 ;
        RECT 163.360 55.930 163.690 56.260 ;
        RECT 143.505 54.975 143.860 55.290 ;
        RECT 143.530 54.960 143.860 54.975 ;
        RECT 144.580 54.960 144.910 55.290 ;
        RECT 147.815 55.130 148.170 55.460 ;
        RECT 147.815 55.120 148.115 55.130 ;
        RECT 150.260 55.125 150.590 55.455 ;
        RECT 144.595 53.745 144.895 54.960 ;
        RECT 144.580 53.415 144.910 53.745 ;
        RECT 148.725 53.560 149.025 54.620 ;
        RECT 144.595 52.180 144.895 53.415 ;
        RECT 148.690 53.230 149.025 53.560 ;
        RECT 143.605 51.550 143.935 51.880 ;
        RECT 143.620 50.020 143.920 51.550 ;
        RECT 148.725 51.530 149.025 53.230 ;
        RECT 149.475 51.865 149.805 51.880 ;
        RECT 150.275 51.865 150.575 55.125 ;
        RECT 149.475 51.565 150.575 51.865 ;
        RECT 149.475 51.550 149.805 51.565 ;
        RECT 148.705 51.200 149.035 51.530 ;
        RECT 145.475 50.850 145.805 51.180 ;
        RECT 145.505 50.550 145.805 50.850 ;
        RECT 145.505 50.465 146.235 50.550 ;
        RECT 145.505 50.250 146.265 50.465 ;
        RECT 145.950 50.030 146.265 50.250 ;
        RECT 143.620 49.690 143.965 50.020 ;
        RECT 145.950 49.865 146.280 50.030 ;
        RECT 149.495 49.990 149.795 51.550 ;
        RECT 151.645 51.180 151.945 55.930 ;
        RECT 163.375 54.555 163.675 55.930 ;
        RECT 166.095 55.015 166.425 55.805 ;
        RECT 163.350 54.225 163.680 54.555 ;
        RECT 152.660 51.200 152.990 51.530 ;
        RECT 161.365 51.500 161.695 51.830 ;
        RECT 151.035 50.860 151.945 51.180 ;
        RECT 151.035 50.850 151.365 50.860 ;
        RECT 145.920 49.700 146.280 49.865 ;
        RECT 143.620 48.820 143.920 49.690 ;
        RECT 145.920 48.825 146.220 49.700 ;
        RECT 149.480 49.660 149.810 49.990 ;
        RECT 143.605 48.490 143.935 48.820 ;
        RECT 145.920 48.495 146.265 48.825 ;
        RECT 143.620 46.920 143.920 48.490 ;
        RECT 145.920 46.920 146.220 48.495 ;
        RECT 149.495 48.370 149.795 49.660 ;
        RECT 151.050 49.130 151.350 50.850 ;
        RECT 151.050 48.800 151.405 49.130 ;
        RECT 149.480 48.040 149.810 48.370 ;
        RECT 143.620 46.615 144.030 46.920 ;
        RECT 143.700 46.590 144.030 46.615 ;
        RECT 145.795 46.615 146.220 46.920 ;
        RECT 149.495 46.690 149.795 48.040 ;
        RECT 151.050 47.480 151.350 48.800 ;
        RECT 152.675 48.675 152.975 51.200 ;
        RECT 161.380 50.590 161.680 51.500 ;
        RECT 163.375 51.405 163.675 54.225 ;
        RECT 162.650 51.105 163.690 51.405 ;
        RECT 162.650 51.075 162.980 51.105 ;
        RECT 163.360 51.075 163.690 51.105 ;
        RECT 166.110 50.590 166.410 55.015 ;
        RECT 168.185 53.235 168.515 53.565 ;
        RECT 161.365 50.260 161.695 50.590 ;
        RECT 166.080 50.260 166.410 50.590 ;
        RECT 152.660 48.345 152.990 48.675 ;
        RECT 151.035 47.150 151.365 47.480 ;
        RECT 145.795 46.590 146.125 46.615 ;
        RECT 143.715 41.285 144.015 46.590 ;
        RECT 145.810 41.285 146.110 46.590 ;
        RECT 149.480 46.360 149.810 46.690 ;
        RECT 149.495 44.650 149.795 46.360 ;
        RECT 151.050 45.530 151.350 47.150 ;
        RECT 152.675 46.230 152.975 48.345 ;
        RECT 151.035 45.200 151.365 45.530 ;
        RECT 154.450 45.200 154.780 45.530 ;
        RECT 149.480 44.320 149.810 44.650 ;
        RECT 150.535 44.320 150.865 44.650 ;
        RECT 150.550 42.070 150.850 44.320 ;
        RECT 154.465 42.070 154.765 45.200 ;
        RECT 150.535 41.740 150.865 42.070 ;
        RECT 154.450 41.740 154.780 42.070 ;
        RECT 143.700 40.955 144.030 41.285 ;
        RECT 145.795 40.955 146.125 41.285 ;
        RECT 161.685 32.650 162.585 49.850 ;
        RECT 168.200 49.830 168.500 53.235 ;
        RECT 169.125 51.575 169.455 51.905 ;
        RECT 168.185 49.500 168.515 49.830 ;
        RECT 169.140 49.480 169.440 51.575 ;
        RECT 165.980 32.770 166.880 49.480 ;
        RECT 169.125 49.150 169.455 49.480 ;
        RECT 110.970 26.540 111.670 26.885 ;
        RECT 103.840 25.960 104.610 26.330 ;
        RECT 109.745 25.960 110.520 26.330 ;
        RECT 94.675 25.450 95.445 25.820 ;
        RECT 99.270 25.450 100.040 25.820 ;
        RECT 93.530 23.805 94.295 25.310 ;
        RECT 93.530 23.435 94.300 23.805 ;
        RECT 93.530 22.030 94.295 23.435 ;
        RECT 94.870 22.135 95.250 25.450 ;
        RECT 95.820 23.790 96.585 25.310 ;
        RECT 98.110 23.790 98.875 25.310 ;
        RECT 95.820 23.420 96.590 23.790 ;
        RECT 98.110 23.420 98.880 23.790 ;
        RECT 95.820 22.030 96.585 23.420 ;
        RECT 98.110 22.030 98.875 23.420 ;
        RECT 99.450 22.135 99.830 25.450 ;
        RECT 100.400 23.790 101.165 25.310 ;
        RECT 102.690 23.790 103.455 25.310 ;
        RECT 100.400 23.420 101.170 23.790 ;
        RECT 102.690 23.420 103.460 23.790 ;
        RECT 100.400 22.030 101.165 23.420 ;
        RECT 102.690 22.030 103.455 23.420 ;
        RECT 104.030 22.135 104.410 25.960 ;
        RECT 110.970 25.820 111.350 26.540 ;
        RECT 113.005 25.960 113.775 26.330 ;
        RECT 108.430 25.450 109.200 25.820 ;
        RECT 110.805 25.450 111.580 25.820 ;
        RECT 104.980 23.790 105.745 25.310 ;
        RECT 107.270 23.790 108.035 25.310 ;
        RECT 104.980 23.420 105.750 23.790 ;
        RECT 107.270 23.420 108.040 23.790 ;
        RECT 104.980 22.030 105.745 23.420 ;
        RECT 107.270 22.030 108.035 23.420 ;
        RECT 108.610 22.135 108.990 25.450 ;
        RECT 109.560 23.790 110.325 25.310 ;
        RECT 111.850 23.790 112.615 25.310 ;
        RECT 109.560 23.420 110.330 23.790 ;
        RECT 111.850 23.420 112.620 23.790 ;
        RECT 109.560 22.030 110.325 23.420 ;
        RECT 111.850 22.030 112.615 23.420 ;
        RECT 113.190 22.135 113.570 25.960 ;
        RECT 117.560 25.450 118.330 25.820 ;
        RECT 122.150 25.450 122.920 25.820 ;
        RECT 114.140 23.790 114.905 25.310 ;
        RECT 116.430 23.790 117.195 25.310 ;
        RECT 114.140 23.420 114.910 23.790 ;
        RECT 116.430 23.420 117.200 23.790 ;
        RECT 114.140 22.030 114.905 23.420 ;
        RECT 93.530 21.660 94.300 22.030 ;
        RECT 95.820 21.660 96.590 22.030 ;
        RECT 98.110 21.660 98.880 22.030 ;
        RECT 100.400 21.660 101.170 22.030 ;
        RECT 102.690 21.660 103.460 22.030 ;
        RECT 104.980 21.660 105.750 22.030 ;
        RECT 107.270 21.660 108.040 22.030 ;
        RECT 109.560 21.660 110.330 22.030 ;
        RECT 111.850 21.660 112.620 22.030 ;
        RECT 114.135 21.660 114.905 22.030 ;
        RECT 93.530 20.145 94.295 21.660 ;
        RECT 95.820 20.145 96.585 21.660 ;
        RECT 98.110 20.145 98.875 21.660 ;
        RECT 100.400 20.145 101.165 21.660 ;
        RECT 102.690 20.145 103.455 21.660 ;
        RECT 104.980 20.145 105.745 21.660 ;
        RECT 107.270 20.145 108.035 21.660 ;
        RECT 109.560 20.145 110.325 21.660 ;
        RECT 111.850 20.145 112.615 21.660 ;
        RECT 114.140 20.145 114.905 21.660 ;
        RECT 116.430 22.030 117.195 23.420 ;
        RECT 117.770 22.135 118.150 25.450 ;
        RECT 118.720 23.790 119.485 25.310 ;
        RECT 121.010 23.790 121.775 25.310 ;
        RECT 118.720 23.420 119.490 23.790 ;
        RECT 121.010 23.420 121.780 23.790 ;
        RECT 118.720 22.030 119.485 23.420 ;
        RECT 121.010 22.030 121.775 23.420 ;
        RECT 122.350 22.135 122.730 25.450 ;
        RECT 123.300 23.790 124.065 25.310 ;
        RECT 123.300 23.420 124.070 23.790 ;
        RECT 123.300 22.030 124.065 23.420 ;
        RECT 116.430 21.660 117.200 22.030 ;
        RECT 118.720 21.660 119.490 22.030 ;
        RECT 121.010 21.660 121.780 22.030 ;
        RECT 123.300 21.660 124.070 22.030 ;
        RECT 116.430 20.145 117.195 21.660 ;
        RECT 118.720 20.145 119.485 21.660 ;
        RECT 121.010 20.145 121.775 21.660 ;
        RECT 123.300 20.145 124.065 21.660 ;
      LAYER met4 ;
        RECT 108.690 30.045 109.170 46.325 ;
  END
END tt_um_SAR_ADC
END LIBRARY

